VERSION 5.8 ;
BUSBITCHARS "[]" ;
DIVIDERCHAR "/" ;
UNITS
    DATABASE MICRONS 1000 ;
END UNITS

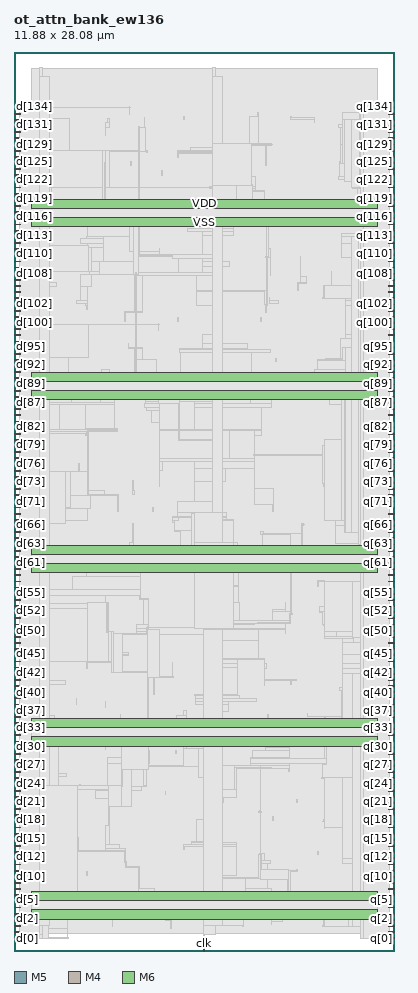
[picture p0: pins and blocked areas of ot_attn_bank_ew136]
MACRO ot_attn_bank_ew136
  FOREIGN ot_attn_bank_ew136 0 0 ;
  CLASS BLOCK ;
  SIZE 11.88 BY 28.08 ;
  PIN clk
    DIRECTION INPUT ;
    USE SIGNAL ;
    PORT
      LAYER M5 ;
        RECT  5.904 0 5.928 0.192 ;
    END
  END clk
  PIN d[0]
    DIRECTION INPUT ;
    USE SIGNAL ;
    PORT
      LAYER M4 ;
        RECT  0 0.384 0.192 0.408 ;
    END
  END d[0]
  PIN d[100]
    DIRECTION INPUT ;
    USE SIGNAL ;
    PORT
      LAYER M4 ;
        RECT  0 19.584 0.192 19.608 ;
    END
  END d[100]
  PIN d[101]
    DIRECTION INPUT ;
    USE SIGNAL ;
    PORT
      LAYER M4 ;
        RECT  0 19.776 0.192 19.8 ;
    END
  END d[101]
  PIN d[102]
    DIRECTION INPUT ;
    USE SIGNAL ;
    PORT
      LAYER M4 ;
        RECT  0 19.968 0.192 19.992 ;
    END
  END d[102]
  PIN d[103]
    DIRECTION INPUT ;
    USE SIGNAL ;
    PORT
      LAYER M4 ;
        RECT  0 20.16 0.192 20.184 ;
    END
  END d[103]
  PIN d[104]
    DIRECTION INPUT ;
    USE SIGNAL ;
    PORT
      LAYER M4 ;
        RECT  0 20.352 0.192 20.376 ;
    END
  END d[104]
  PIN d[105]
    DIRECTION INPUT ;
    USE SIGNAL ;
    PORT
      LAYER M4 ;
        RECT  0 20.544 0.192 20.568 ;
    END
  END d[105]
  PIN d[106]
    DIRECTION INPUT ;
    USE SIGNAL ;
    PORT
      LAYER M4 ;
        RECT  0 20.736 0.192 20.76 ;
    END
  END d[106]
  PIN d[107]
    DIRECTION INPUT ;
    USE SIGNAL ;
    PORT
      LAYER M4 ;
        RECT  0 20.928 0.192 20.952 ;
    END
  END d[107]
  PIN d[108]
    DIRECTION INPUT ;
    USE SIGNAL ;
    PORT
      LAYER M4 ;
        RECT  0 21.12 0.192 21.144 ;
    END
  END d[108]
  PIN d[109]
    DIRECTION INPUT ;
    USE SIGNAL ;
    PORT
      LAYER M4 ;
        RECT  0 21.312 0.192 21.336 ;
    END
  END d[109]
  PIN d[10]
    DIRECTION INPUT ;
    USE SIGNAL ;
    PORT
      LAYER M4 ;
        RECT  0 2.304 0.192 2.328 ;
    END
  END d[10]
  PIN d[110]
    DIRECTION INPUT ;
    USE SIGNAL ;
    PORT
      LAYER M4 ;
        RECT  0 21.504 0.192 21.528 ;
    END
  END d[110]
  PIN d[111]
    DIRECTION INPUT ;
    USE SIGNAL ;
    PORT
      LAYER M4 ;
        RECT  0 21.696 0.192 21.72 ;
    END
  END d[111]
  PIN d[112]
    DIRECTION INPUT ;
    USE SIGNAL ;
    PORT
      LAYER M4 ;
        RECT  0 21.888 0.192 21.912 ;
    END
  END d[112]
  PIN d[113]
    DIRECTION INPUT ;
    USE SIGNAL ;
    PORT
      LAYER M4 ;
        RECT  0 22.08 0.192 22.104 ;
    END
  END d[113]
  PIN d[114]
    DIRECTION INPUT ;
    USE SIGNAL ;
    PORT
      LAYER M4 ;
        RECT  0 22.272 0.192 22.296 ;
    END
  END d[114]
  PIN d[115]
    DIRECTION INPUT ;
    USE SIGNAL ;
    PORT
      LAYER M4 ;
        RECT  0 22.464 0.192 22.488 ;
    END
  END d[115]
  PIN d[116]
    DIRECTION INPUT ;
    USE SIGNAL ;
    PORT
      LAYER M4 ;
        RECT  0 22.656 0.192 22.68 ;
    END
  END d[116]
  PIN d[117]
    DIRECTION INPUT ;
    USE SIGNAL ;
    PORT
      LAYER M4 ;
        RECT  0 22.848 0.192 22.872 ;
    END
  END d[117]
  PIN d[118]
    DIRECTION INPUT ;
    USE SIGNAL ;
    PORT
      LAYER M4 ;
        RECT  0 23.04 0.192 23.064 ;
    END
  END d[118]
  PIN d[119]
    DIRECTION INPUT ;
    USE SIGNAL ;
    PORT
      LAYER M4 ;
        RECT  0 23.232 0.192 23.256 ;
    END
  END d[119]
  PIN d[11]
    DIRECTION INPUT ;
    USE SIGNAL ;
    PORT
      LAYER M4 ;
        RECT  0 2.496 0.192 2.52 ;
    END
  END d[11]
  PIN d[120]
    DIRECTION INPUT ;
    USE SIGNAL ;
    PORT
      LAYER M4 ;
        RECT  0 23.424 0.192 23.448 ;
    END
  END d[120]
  PIN d[121]
    DIRECTION INPUT ;
    USE SIGNAL ;
    PORT
      LAYER M4 ;
        RECT  0 23.616 0.192 23.64 ;
    END
  END d[121]
  PIN d[122]
    DIRECTION INPUT ;
    USE SIGNAL ;
    PORT
      LAYER M4 ;
        RECT  0 23.808 0.192 23.832 ;
    END
  END d[122]
  PIN d[123]
    DIRECTION INPUT ;
    USE SIGNAL ;
    PORT
      LAYER M4 ;
        RECT  0 24 0.192 24.024 ;
    END
  END d[123]
  PIN d[124]
    DIRECTION INPUT ;
    USE SIGNAL ;
    PORT
      LAYER M4 ;
        RECT  0 24.192 0.192 24.216 ;
    END
  END d[124]
  PIN d[125]
    DIRECTION INPUT ;
    USE SIGNAL ;
    PORT
      LAYER M4 ;
        RECT  0 24.384 0.192 24.408 ;
    END
  END d[125]
  PIN d[126]
    DIRECTION INPUT ;
    USE SIGNAL ;
    PORT
      LAYER M4 ;
        RECT  0 24.576 0.192 24.6 ;
    END
  END d[126]
  PIN d[127]
    DIRECTION INPUT ;
    USE SIGNAL ;
    PORT
      LAYER M4 ;
        RECT  0 24.768 0.192 24.792 ;
    END
  END d[127]
  PIN d[128]
    DIRECTION INPUT ;
    USE SIGNAL ;
    PORT
      LAYER M4 ;
        RECT  0 24.96 0.192 24.984 ;
    END
  END d[128]
  PIN d[129]
    DIRECTION INPUT ;
    USE SIGNAL ;
    PORT
      LAYER M4 ;
        RECT  0 25.152 0.192 25.176 ;
    END
  END d[129]
  PIN d[12]
    DIRECTION INPUT ;
    USE SIGNAL ;
    PORT
      LAYER M4 ;
        RECT  0 2.688 0.192 2.712 ;
    END
  END d[12]
  PIN d[130]
    DIRECTION INPUT ;
    USE SIGNAL ;
    PORT
      LAYER M4 ;
        RECT  0 25.344 0.192 25.368 ;
    END
  END d[130]
  PIN d[131]
    DIRECTION INPUT ;
    USE SIGNAL ;
    PORT
      LAYER M4 ;
        RECT  0 25.536 0.192 25.56 ;
    END
  END d[131]
  PIN d[132]
    DIRECTION INPUT ;
    USE SIGNAL ;
    PORT
      LAYER M4 ;
        RECT  0 25.728 0.192 25.752 ;
    END
  END d[132]
  PIN d[133]
    DIRECTION INPUT ;
    USE SIGNAL ;
    PORT
      LAYER M4 ;
        RECT  0 25.92 0.192 25.944 ;
    END
  END d[133]
  PIN d[134]
    DIRECTION INPUT ;
    USE SIGNAL ;
    PORT
      LAYER M4 ;
        RECT  0 26.112 0.192 26.136 ;
    END
  END d[134]
  PIN d[135]
    DIRECTION INPUT ;
    USE SIGNAL ;
    PORT
      LAYER M4 ;
        RECT  0 26.304 0.192 26.328 ;
    END
  END d[135]
  PIN d[13]
    DIRECTION INPUT ;
    USE SIGNAL ;
    PORT
      LAYER M4 ;
        RECT  0 2.88 0.192 2.904 ;
    END
  END d[13]
  PIN d[14]
    DIRECTION INPUT ;
    USE SIGNAL ;
    PORT
      LAYER M4 ;
        RECT  0 3.072 0.192 3.096 ;
    END
  END d[14]
  PIN d[15]
    DIRECTION INPUT ;
    USE SIGNAL ;
    PORT
      LAYER M4 ;
        RECT  0 3.264 0.192 3.288 ;
    END
  END d[15]
  PIN d[16]
    DIRECTION INPUT ;
    USE SIGNAL ;
    PORT
      LAYER M4 ;
        RECT  0 3.456 0.192 3.48 ;
    END
  END d[16]
  PIN d[17]
    DIRECTION INPUT ;
    USE SIGNAL ;
    PORT
      LAYER M4 ;
        RECT  0 3.648 0.192 3.672 ;
    END
  END d[17]
  PIN d[18]
    DIRECTION INPUT ;
    USE SIGNAL ;
    PORT
      LAYER M4 ;
        RECT  0 3.84 0.192 3.864 ;
    END
  END d[18]
  PIN d[19]
    DIRECTION INPUT ;
    USE SIGNAL ;
    PORT
      LAYER M4 ;
        RECT  0 4.032 0.192 4.056 ;
    END
  END d[19]
  PIN d[1]
    DIRECTION INPUT ;
    USE SIGNAL ;
    PORT
      LAYER M4 ;
        RECT  0 0.576 0.192 0.6 ;
    END
  END d[1]
  PIN d[20]
    DIRECTION INPUT ;
    USE SIGNAL ;
    PORT
      LAYER M4 ;
        RECT  0 4.224 0.192 4.248 ;
    END
  END d[20]
  PIN d[21]
    DIRECTION INPUT ;
    USE SIGNAL ;
    PORT
      LAYER M4 ;
        RECT  0 4.416 0.192 4.44 ;
    END
  END d[21]
  PIN d[22]
    DIRECTION INPUT ;
    USE SIGNAL ;
    PORT
      LAYER M4 ;
        RECT  0 4.608 0.192 4.632 ;
    END
  END d[22]
  PIN d[23]
    DIRECTION INPUT ;
    USE SIGNAL ;
    PORT
      LAYER M4 ;
        RECT  0 4.8 0.192 4.824 ;
    END
  END d[23]
  PIN d[24]
    DIRECTION INPUT ;
    USE SIGNAL ;
    PORT
      LAYER M4 ;
        RECT  0 4.992 0.192 5.016 ;
    END
  END d[24]
  PIN d[25]
    DIRECTION INPUT ;
    USE SIGNAL ;
    PORT
      LAYER M4 ;
        RECT  0 5.184 0.192 5.208 ;
    END
  END d[25]
  PIN d[26]
    DIRECTION INPUT ;
    USE SIGNAL ;
    PORT
      LAYER M4 ;
        RECT  0 5.376 0.192 5.4 ;
    END
  END d[26]
  PIN d[27]
    DIRECTION INPUT ;
    USE SIGNAL ;
    PORT
      LAYER M4 ;
        RECT  0 5.568 0.192 5.592 ;
    END
  END d[27]
  PIN d[28]
    DIRECTION INPUT ;
    USE SIGNAL ;
    PORT
      LAYER M4 ;
        RECT  0 5.76 0.192 5.784 ;
    END
  END d[28]
  PIN d[29]
    DIRECTION INPUT ;
    USE SIGNAL ;
    PORT
      LAYER M4 ;
        RECT  0 5.952 0.192 5.976 ;
    END
  END d[29]
  PIN d[2]
    DIRECTION INPUT ;
    USE SIGNAL ;
    PORT
      LAYER M4 ;
        RECT  0 0.768 0.192 0.792 ;
    END
  END d[2]
  PIN d[30]
    DIRECTION INPUT ;
    USE SIGNAL ;
    PORT
      LAYER M4 ;
        RECT  0 6.144 0.192 6.168 ;
    END
  END d[30]
  PIN d[31]
    DIRECTION INPUT ;
    USE SIGNAL ;
    PORT
      LAYER M4 ;
        RECT  0 6.336 0.192 6.36 ;
    END
  END d[31]
  PIN d[32]
    DIRECTION INPUT ;
    USE SIGNAL ;
    PORT
      LAYER M4 ;
        RECT  0 6.528 0.192 6.552 ;
    END
  END d[32]
  PIN d[33]
    DIRECTION INPUT ;
    USE SIGNAL ;
    PORT
      LAYER M4 ;
        RECT  0 6.72 0.192 6.744 ;
    END
  END d[33]
  PIN d[34]
    DIRECTION INPUT ;
    USE SIGNAL ;
    PORT
      LAYER M4 ;
        RECT  0 6.912 0.192 6.936 ;
    END
  END d[34]
  PIN d[35]
    DIRECTION INPUT ;
    USE SIGNAL ;
    PORT
      LAYER M4 ;
        RECT  0 7.104 0.192 7.128 ;
    END
  END d[35]
  PIN d[36]
    DIRECTION INPUT ;
    USE SIGNAL ;
    PORT
      LAYER M4 ;
        RECT  0 7.296 0.192 7.32 ;
    END
  END d[36]
  PIN d[37]
    DIRECTION INPUT ;
    USE SIGNAL ;
    PORT
      LAYER M4 ;
        RECT  0 7.488 0.192 7.512 ;
    END
  END d[37]
  PIN d[38]
    DIRECTION INPUT ;
    USE SIGNAL ;
    PORT
      LAYER M4 ;
        RECT  0 7.68 0.192 7.704 ;
    END
  END d[38]
  PIN d[39]
    DIRECTION INPUT ;
    USE SIGNAL ;
    PORT
      LAYER M4 ;
        RECT  0 7.872 0.192 7.896 ;
    END
  END d[39]
  PIN d[3]
    DIRECTION INPUT ;
    USE SIGNAL ;
    PORT
      LAYER M4 ;
        RECT  0 0.96 0.192 0.984 ;
    END
  END d[3]
  PIN d[40]
    DIRECTION INPUT ;
    USE SIGNAL ;
    PORT
      LAYER M4 ;
        RECT  0 8.064 0.192 8.088 ;
    END
  END d[40]
  PIN d[41]
    DIRECTION INPUT ;
    USE SIGNAL ;
    PORT
      LAYER M4 ;
        RECT  0 8.256 0.192 8.28 ;
    END
  END d[41]
  PIN d[42]
    DIRECTION INPUT ;
    USE SIGNAL ;
    PORT
      LAYER M4 ;
        RECT  0 8.448 0.192 8.472 ;
    END
  END d[42]
  PIN d[43]
    DIRECTION INPUT ;
    USE SIGNAL ;
    PORT
      LAYER M4 ;
        RECT  0 8.64 0.192 8.664 ;
    END
  END d[43]
  PIN d[44]
    DIRECTION INPUT ;
    USE SIGNAL ;
    PORT
      LAYER M4 ;
        RECT  0 8.832 0.192 8.856 ;
    END
  END d[44]
  PIN d[45]
    DIRECTION INPUT ;
    USE SIGNAL ;
    PORT
      LAYER M4 ;
        RECT  0 9.024 0.192 9.048 ;
    END
  END d[45]
  PIN d[46]
    DIRECTION INPUT ;
    USE SIGNAL ;
    PORT
      LAYER M4 ;
        RECT  0 9.216 0.192 9.24 ;
    END
  END d[46]
  PIN d[47]
    DIRECTION INPUT ;
    USE SIGNAL ;
    PORT
      LAYER M4 ;
        RECT  0 9.408 0.192 9.432 ;
    END
  END d[47]
  PIN d[48]
    DIRECTION INPUT ;
    USE SIGNAL ;
    PORT
      LAYER M4 ;
        RECT  0 9.6 0.192 9.624 ;
    END
  END d[48]
  PIN d[49]
    DIRECTION INPUT ;
    USE SIGNAL ;
    PORT
      LAYER M4 ;
        RECT  0 9.792 0.192 9.816 ;
    END
  END d[49]
  PIN d[4]
    DIRECTION INPUT ;
    USE SIGNAL ;
    PORT
      LAYER M4 ;
        RECT  0 1.152 0.192 1.176 ;
    END
  END d[4]
  PIN d[50]
    DIRECTION INPUT ;
    USE SIGNAL ;
    PORT
      LAYER M4 ;
        RECT  0 9.984 0.192 10.008 ;
    END
  END d[50]
  PIN d[51]
    DIRECTION INPUT ;
    USE SIGNAL ;
    PORT
      LAYER M4 ;
        RECT  0 10.176 0.192 10.2 ;
    END
  END d[51]
  PIN d[52]
    DIRECTION INPUT ;
    USE SIGNAL ;
    PORT
      LAYER M4 ;
        RECT  0 10.368 0.192 10.392 ;
    END
  END d[52]
  PIN d[53]
    DIRECTION INPUT ;
    USE SIGNAL ;
    PORT
      LAYER M4 ;
        RECT  0 10.56 0.192 10.584 ;
    END
  END d[53]
  PIN d[54]
    DIRECTION INPUT ;
    USE SIGNAL ;
    PORT
      LAYER M4 ;
        RECT  0 10.752 0.192 10.776 ;
    END
  END d[54]
  PIN d[55]
    DIRECTION INPUT ;
    USE SIGNAL ;
    PORT
      LAYER M4 ;
        RECT  0 10.944 0.192 10.968 ;
    END
  END d[55]
  PIN d[56]
    DIRECTION INPUT ;
    USE SIGNAL ;
    PORT
      LAYER M4 ;
        RECT  0 11.136 0.192 11.16 ;
    END
  END d[56]
  PIN d[57]
    DIRECTION INPUT ;
    USE SIGNAL ;
    PORT
      LAYER M4 ;
        RECT  0 11.328 0.192 11.352 ;
    END
  END d[57]
  PIN d[58]
    DIRECTION INPUT ;
    USE SIGNAL ;
    PORT
      LAYER M4 ;
        RECT  0 11.52 0.192 11.544 ;
    END
  END d[58]
  PIN d[59]
    DIRECTION INPUT ;
    USE SIGNAL ;
    PORT
      LAYER M4 ;
        RECT  0 11.712 0.192 11.736 ;
    END
  END d[59]
  PIN d[5]
    DIRECTION INPUT ;
    USE SIGNAL ;
    PORT
      LAYER M4 ;
        RECT  0 1.344 0.192 1.368 ;
    END
  END d[5]
  PIN d[60]
    DIRECTION INPUT ;
    USE SIGNAL ;
    PORT
      LAYER M4 ;
        RECT  0 11.904 0.192 11.928 ;
    END
  END d[60]
  PIN d[61]
    DIRECTION INPUT ;
    USE SIGNAL ;
    PORT
      LAYER M4 ;
        RECT  0 12.096 0.192 12.12 ;
    END
  END d[61]
  PIN d[62]
    DIRECTION INPUT ;
    USE SIGNAL ;
    PORT
      LAYER M4 ;
        RECT  0 12.288 0.192 12.312 ;
    END
  END d[62]
  PIN d[63]
    DIRECTION INPUT ;
    USE SIGNAL ;
    PORT
      LAYER M4 ;
        RECT  0 12.48 0.192 12.504 ;
    END
  END d[63]
  PIN d[64]
    DIRECTION INPUT ;
    USE SIGNAL ;
    PORT
      LAYER M4 ;
        RECT  0 12.672 0.192 12.696 ;
    END
  END d[64]
  PIN d[65]
    DIRECTION INPUT ;
    USE SIGNAL ;
    PORT
      LAYER M4 ;
        RECT  0 12.864 0.192 12.888 ;
    END
  END d[65]
  PIN d[66]
    DIRECTION INPUT ;
    USE SIGNAL ;
    PORT
      LAYER M4 ;
        RECT  0 13.056 0.192 13.08 ;
    END
  END d[66]
  PIN d[67]
    DIRECTION INPUT ;
    USE SIGNAL ;
    PORT
      LAYER M4 ;
        RECT  0 13.248 0.192 13.272 ;
    END
  END d[67]
  PIN d[68]
    DIRECTION INPUT ;
    USE SIGNAL ;
    PORT
      LAYER M4 ;
        RECT  0 13.44 0.192 13.464 ;
    END
  END d[68]
  PIN d[69]
    DIRECTION INPUT ;
    USE SIGNAL ;
    PORT
      LAYER M4 ;
        RECT  0 13.632 0.192 13.656 ;
    END
  END d[69]
  PIN d[6]
    DIRECTION INPUT ;
    USE SIGNAL ;
    PORT
      LAYER M4 ;
        RECT  0 1.536 0.192 1.56 ;
    END
  END d[6]
  PIN d[70]
    DIRECTION INPUT ;
    USE SIGNAL ;
    PORT
      LAYER M4 ;
        RECT  0 13.824 0.192 13.848 ;
    END
  END d[70]
  PIN d[71]
    DIRECTION INPUT ;
    USE SIGNAL ;
    PORT
      LAYER M4 ;
        RECT  0 14.016 0.192 14.04 ;
    END
  END d[71]
  PIN d[72]
    DIRECTION INPUT ;
    USE SIGNAL ;
    PORT
      LAYER M4 ;
        RECT  0 14.208 0.192 14.232 ;
    END
  END d[72]
  PIN d[73]
    DIRECTION INPUT ;
    USE SIGNAL ;
    PORT
      LAYER M4 ;
        RECT  0 14.4 0.192 14.424 ;
    END
  END d[73]
  PIN d[74]
    DIRECTION INPUT ;
    USE SIGNAL ;
    PORT
      LAYER M4 ;
        RECT  0 14.592 0.192 14.616 ;
    END
  END d[74]
  PIN d[75]
    DIRECTION INPUT ;
    USE SIGNAL ;
    PORT
      LAYER M4 ;
        RECT  0 14.784 0.192 14.808 ;
    END
  END d[75]
  PIN d[76]
    DIRECTION INPUT ;
    USE SIGNAL ;
    PORT
      LAYER M4 ;
        RECT  0 14.976 0.192 15 ;
    END
  END d[76]
  PIN d[77]
    DIRECTION INPUT ;
    USE SIGNAL ;
    PORT
      LAYER M4 ;
        RECT  0 15.168 0.192 15.192 ;
    END
  END d[77]
  PIN d[78]
    DIRECTION INPUT ;
    USE SIGNAL ;
    PORT
      LAYER M4 ;
        RECT  0 15.36 0.192 15.384 ;
    END
  END d[78]
  PIN d[79]
    DIRECTION INPUT ;
    USE SIGNAL ;
    PORT
      LAYER M4 ;
        RECT  0 15.552 0.192 15.576 ;
    END
  END d[79]
  PIN d[7]
    DIRECTION INPUT ;
    USE SIGNAL ;
    PORT
      LAYER M4 ;
        RECT  0 1.728 0.192 1.752 ;
    END
  END d[7]
  PIN d[80]
    DIRECTION INPUT ;
    USE SIGNAL ;
    PORT
      LAYER M4 ;
        RECT  0 15.744 0.192 15.768 ;
    END
  END d[80]
  PIN d[81]
    DIRECTION INPUT ;
    USE SIGNAL ;
    PORT
      LAYER M4 ;
        RECT  0 15.936 0.192 15.96 ;
    END
  END d[81]
  PIN d[82]
    DIRECTION INPUT ;
    USE SIGNAL ;
    PORT
      LAYER M4 ;
        RECT  0 16.128 0.192 16.152 ;
    END
  END d[82]
  PIN d[83]
    DIRECTION INPUT ;
    USE SIGNAL ;
    PORT
      LAYER M4 ;
        RECT  0 16.32 0.192 16.344 ;
    END
  END d[83]
  PIN d[84]
    DIRECTION INPUT ;
    USE SIGNAL ;
    PORT
      LAYER M4 ;
        RECT  0 16.512 0.192 16.536 ;
    END
  END d[84]
  PIN d[85]
    DIRECTION INPUT ;
    USE SIGNAL ;
    PORT
      LAYER M4 ;
        RECT  0 16.704 0.192 16.728 ;
    END
  END d[85]
  PIN d[86]
    DIRECTION INPUT ;
    USE SIGNAL ;
    PORT
      LAYER M4 ;
        RECT  0 16.896 0.192 16.92 ;
    END
  END d[86]
  PIN d[87]
    DIRECTION INPUT ;
    USE SIGNAL ;
    PORT
      LAYER M4 ;
        RECT  0 17.088 0.192 17.112 ;
    END
  END d[87]
  PIN d[88]
    DIRECTION INPUT ;
    USE SIGNAL ;
    PORT
      LAYER M4 ;
        RECT  0 17.28 0.192 17.304 ;
    END
  END d[88]
  PIN d[89]
    DIRECTION INPUT ;
    USE SIGNAL ;
    PORT
      LAYER M4 ;
        RECT  0 17.472 0.192 17.496 ;
    END
  END d[89]
  PIN d[8]
    DIRECTION INPUT ;
    USE SIGNAL ;
    PORT
      LAYER M4 ;
        RECT  0 1.92 0.192 1.944 ;
    END
  END d[8]
  PIN d[90]
    DIRECTION INPUT ;
    USE SIGNAL ;
    PORT
      LAYER M4 ;
        RECT  0 17.664 0.192 17.688 ;
    END
  END d[90]
  PIN d[91]
    DIRECTION INPUT ;
    USE SIGNAL ;
    PORT
      LAYER M4 ;
        RECT  0 17.856 0.192 17.88 ;
    END
  END d[91]
  PIN d[92]
    DIRECTION INPUT ;
    USE SIGNAL ;
    PORT
      LAYER M4 ;
        RECT  0 18.048 0.192 18.072 ;
    END
  END d[92]
  PIN d[93]
    DIRECTION INPUT ;
    USE SIGNAL ;
    PORT
      LAYER M4 ;
        RECT  0 18.24 0.192 18.264 ;
    END
  END d[93]
  PIN d[94]
    DIRECTION INPUT ;
    USE SIGNAL ;
    PORT
      LAYER M4 ;
        RECT  0 18.432 0.192 18.456 ;
    END
  END d[94]
  PIN d[95]
    DIRECTION INPUT ;
    USE SIGNAL ;
    PORT
      LAYER M4 ;
        RECT  0 18.624 0.192 18.648 ;
    END
  END d[95]
  PIN d[96]
    DIRECTION INPUT ;
    USE SIGNAL ;
    PORT
      LAYER M4 ;
        RECT  0 18.816 0.192 18.84 ;
    END
  END d[96]
  PIN d[97]
    DIRECTION INPUT ;
    USE SIGNAL ;
    PORT
      LAYER M4 ;
        RECT  0 19.008 0.192 19.032 ;
    END
  END d[97]
  PIN d[98]
    DIRECTION INPUT ;
    USE SIGNAL ;
    PORT
      LAYER M4 ;
        RECT  0 19.2 0.192 19.224 ;
    END
  END d[98]
  PIN d[99]
    DIRECTION INPUT ;
    USE SIGNAL ;
    PORT
      LAYER M4 ;
        RECT  0 19.392 0.192 19.416 ;
    END
  END d[99]
  PIN d[9]
    DIRECTION INPUT ;
    USE SIGNAL ;
    PORT
      LAYER M4 ;
        RECT  0 2.112 0.192 2.136 ;
    END
  END d[9]
  PIN q[0]
    DIRECTION OUTPUT ;
    USE SIGNAL ;
    PORT
      LAYER M4 ;
        RECT  11.688 0.384 11.88 0.408 ;
    END
  END q[0]
  PIN q[100]
    DIRECTION OUTPUT ;
    USE SIGNAL ;
    PORT
      LAYER M4 ;
        RECT  11.688 19.584 11.88 19.608 ;
    END
  END q[100]
  PIN q[101]
    DIRECTION OUTPUT ;
    USE SIGNAL ;
    PORT
      LAYER M4 ;
        RECT  11.688 19.776 11.88 19.8 ;
    END
  END q[101]
  PIN q[102]
    DIRECTION OUTPUT ;
    USE SIGNAL ;
    PORT
      LAYER M4 ;
        RECT  11.688 19.968 11.88 19.992 ;
    END
  END q[102]
  PIN q[103]
    DIRECTION OUTPUT ;
    USE SIGNAL ;
    PORT
      LAYER M4 ;
        RECT  11.688 20.16 11.88 20.184 ;
    END
  END q[103]
  PIN q[104]
    DIRECTION OUTPUT ;
    USE SIGNAL ;
    PORT
      LAYER M4 ;
        RECT  11.688 20.352 11.88 20.376 ;
    END
  END q[104]
  PIN q[105]
    DIRECTION OUTPUT ;
    USE SIGNAL ;
    PORT
      LAYER M4 ;
        RECT  11.688 20.544 11.88 20.568 ;
    END
  END q[105]
  PIN q[106]
    DIRECTION OUTPUT ;
    USE SIGNAL ;
    PORT
      LAYER M4 ;
        RECT  11.688 20.736 11.88 20.76 ;
    END
  END q[106]
  PIN q[107]
    DIRECTION OUTPUT ;
    USE SIGNAL ;
    PORT
      LAYER M4 ;
        RECT  11.688 20.928 11.88 20.952 ;
    END
  END q[107]
  PIN q[108]
    DIRECTION OUTPUT ;
    USE SIGNAL ;
    PORT
      LAYER M4 ;
        RECT  11.688 21.12 11.88 21.144 ;
    END
  END q[108]
  PIN q[109]
    DIRECTION OUTPUT ;
    USE SIGNAL ;
    PORT
      LAYER M4 ;
        RECT  11.688 21.312 11.88 21.336 ;
    END
  END q[109]
  PIN q[10]
    DIRECTION OUTPUT ;
    USE SIGNAL ;
    PORT
      LAYER M4 ;
        RECT  11.688 2.304 11.88 2.328 ;
    END
  END q[10]
  PIN q[110]
    DIRECTION OUTPUT ;
    USE SIGNAL ;
    PORT
      LAYER M4 ;
        RECT  11.688 21.504 11.88 21.528 ;
    END
  END q[110]
  PIN q[111]
    DIRECTION OUTPUT ;
    USE SIGNAL ;
    PORT
      LAYER M4 ;
        RECT  11.688 21.696 11.88 21.72 ;
    END
  END q[111]
  PIN q[112]
    DIRECTION OUTPUT ;
    USE SIGNAL ;
    PORT
      LAYER M4 ;
        RECT  11.688 21.888 11.88 21.912 ;
    END
  END q[112]
  PIN q[113]
    DIRECTION OUTPUT ;
    USE SIGNAL ;
    PORT
      LAYER M4 ;
        RECT  11.688 22.08 11.88 22.104 ;
    END
  END q[113]
  PIN q[114]
    DIRECTION OUTPUT ;
    USE SIGNAL ;
    PORT
      LAYER M4 ;
        RECT  11.688 22.272 11.88 22.296 ;
    END
  END q[114]
  PIN q[115]
    DIRECTION OUTPUT ;
    USE SIGNAL ;
    PORT
      LAYER M4 ;
        RECT  11.688 22.464 11.88 22.488 ;
    END
  END q[115]
  PIN q[116]
    DIRECTION OUTPUT ;
    USE SIGNAL ;
    PORT
      LAYER M4 ;
        RECT  11.688 22.656 11.88 22.68 ;
    END
  END q[116]
  PIN q[117]
    DIRECTION OUTPUT ;
    USE SIGNAL ;
    PORT
      LAYER M4 ;
        RECT  11.688 22.848 11.88 22.872 ;
    END
  END q[117]
  PIN q[118]
    DIRECTION OUTPUT ;
    USE SIGNAL ;
    PORT
      LAYER M4 ;
        RECT  11.688 23.04 11.88 23.064 ;
    END
  END q[118]
  PIN q[119]
    DIRECTION OUTPUT ;
    USE SIGNAL ;
    PORT
      LAYER M4 ;
        RECT  11.688 23.232 11.88 23.256 ;
    END
  END q[119]
  PIN q[11]
    DIRECTION OUTPUT ;
    USE SIGNAL ;
    PORT
      LAYER M4 ;
        RECT  11.688 2.496 11.88 2.52 ;
    END
  END q[11]
  PIN q[120]
    DIRECTION OUTPUT ;
    USE SIGNAL ;
    PORT
      LAYER M4 ;
        RECT  11.688 23.424 11.88 23.448 ;
    END
  END q[120]
  PIN q[121]
    DIRECTION OUTPUT ;
    USE SIGNAL ;
    PORT
      LAYER M4 ;
        RECT  11.688 23.616 11.88 23.64 ;
    END
  END q[121]
  PIN q[122]
    DIRECTION OUTPUT ;
    USE SIGNAL ;
    PORT
      LAYER M4 ;
        RECT  11.688 23.808 11.88 23.832 ;
    END
  END q[122]
  PIN q[123]
    DIRECTION OUTPUT ;
    USE SIGNAL ;
    PORT
      LAYER M4 ;
        RECT  11.688 24 11.88 24.024 ;
    END
  END q[123]
  PIN q[124]
    DIRECTION OUTPUT ;
    USE SIGNAL ;
    PORT
      LAYER M4 ;
        RECT  11.688 24.192 11.88 24.216 ;
    END
  END q[124]
  PIN q[125]
    DIRECTION OUTPUT ;
    USE SIGNAL ;
    PORT
      LAYER M4 ;
        RECT  11.688 24.384 11.88 24.408 ;
    END
  END q[125]
  PIN q[126]
    DIRECTION OUTPUT ;
    USE SIGNAL ;
    PORT
      LAYER M4 ;
        RECT  11.688 24.576 11.88 24.6 ;
    END
  END q[126]
  PIN q[127]
    DIRECTION OUTPUT ;
    USE SIGNAL ;
    PORT
      LAYER M4 ;
        RECT  11.688 24.768 11.88 24.792 ;
    END
  END q[127]
  PIN q[128]
    DIRECTION OUTPUT ;
    USE SIGNAL ;
    PORT
      LAYER M4 ;
        RECT  11.688 24.96 11.88 24.984 ;
    END
  END q[128]
  PIN q[129]
    DIRECTION OUTPUT ;
    USE SIGNAL ;
    PORT
      LAYER M4 ;
        RECT  11.688 25.152 11.88 25.176 ;
    END
  END q[129]
  PIN q[12]
    DIRECTION OUTPUT ;
    USE SIGNAL ;
    PORT
      LAYER M4 ;
        RECT  11.688 2.688 11.88 2.712 ;
    END
  END q[12]
  PIN q[130]
    DIRECTION OUTPUT ;
    USE SIGNAL ;
    PORT
      LAYER M4 ;
        RECT  11.688 25.344 11.88 25.368 ;
    END
  END q[130]
  PIN q[131]
    DIRECTION OUTPUT ;
    USE SIGNAL ;
    PORT
      LAYER M4 ;
        RECT  11.688 25.536 11.88 25.56 ;
    END
  END q[131]
  PIN q[132]
    DIRECTION OUTPUT ;
    USE SIGNAL ;
    PORT
      LAYER M4 ;
        RECT  11.688 25.728 11.88 25.752 ;
    END
  END q[132]
  PIN q[133]
    DIRECTION OUTPUT ;
    USE SIGNAL ;
    PORT
      LAYER M4 ;
        RECT  11.688 25.92 11.88 25.944 ;
    END
  END q[133]
  PIN q[134]
    DIRECTION OUTPUT ;
    USE SIGNAL ;
    PORT
      LAYER M4 ;
        RECT  11.688 26.112 11.88 26.136 ;
    END
  END q[134]
  PIN q[135]
    DIRECTION OUTPUT ;
    USE SIGNAL ;
    PORT
      LAYER M4 ;
        RECT  11.688 26.304 11.88 26.328 ;
    END
  END q[135]
  PIN q[13]
    DIRECTION OUTPUT ;
    USE SIGNAL ;
    PORT
      LAYER M4 ;
        RECT  11.688 2.88 11.88 2.904 ;
    END
  END q[13]
  PIN q[14]
    DIRECTION OUTPUT ;
    USE SIGNAL ;
    PORT
      LAYER M4 ;
        RECT  11.688 3.072 11.88 3.096 ;
    END
  END q[14]
  PIN q[15]
    DIRECTION OUTPUT ;
    USE SIGNAL ;
    PORT
      LAYER M4 ;
        RECT  11.688 3.264 11.88 3.288 ;
    END
  END q[15]
  PIN q[16]
    DIRECTION OUTPUT ;
    USE SIGNAL ;
    PORT
      LAYER M4 ;
        RECT  11.688 3.456 11.88 3.48 ;
    END
  END q[16]
  PIN q[17]
    DIRECTION OUTPUT ;
    USE SIGNAL ;
    PORT
      LAYER M4 ;
        RECT  11.688 3.648 11.88 3.672 ;
    END
  END q[17]
  PIN q[18]
    DIRECTION OUTPUT ;
    USE SIGNAL ;
    PORT
      LAYER M4 ;
        RECT  11.688 3.84 11.88 3.864 ;
    END
  END q[18]
  PIN q[19]
    DIRECTION OUTPUT ;
    USE SIGNAL ;
    PORT
      LAYER M4 ;
        RECT  11.688 4.032 11.88 4.056 ;
    END
  END q[19]
  PIN q[1]
    DIRECTION OUTPUT ;
    USE SIGNAL ;
    PORT
      LAYER M4 ;
        RECT  11.688 0.576 11.88 0.6 ;
    END
  END q[1]
  PIN q[20]
    DIRECTION OUTPUT ;
    USE SIGNAL ;
    PORT
      LAYER M4 ;
        RECT  11.688 4.224 11.88 4.248 ;
    END
  END q[20]
  PIN q[21]
    DIRECTION OUTPUT ;
    USE SIGNAL ;
    PORT
      LAYER M4 ;
        RECT  11.688 4.416 11.88 4.44 ;
    END
  END q[21]
  PIN q[22]
    DIRECTION OUTPUT ;
    USE SIGNAL ;
    PORT
      LAYER M4 ;
        RECT  11.688 4.608 11.88 4.632 ;
    END
  END q[22]
  PIN q[23]
    DIRECTION OUTPUT ;
    USE SIGNAL ;
    PORT
      LAYER M4 ;
        RECT  11.688 4.8 11.88 4.824 ;
    END
  END q[23]
  PIN q[24]
    DIRECTION OUTPUT ;
    USE SIGNAL ;
    PORT
      LAYER M4 ;
        RECT  11.688 4.992 11.88 5.016 ;
    END
  END q[24]
  PIN q[25]
    DIRECTION OUTPUT ;
    USE SIGNAL ;
    PORT
      LAYER M4 ;
        RECT  11.688 5.184 11.88 5.208 ;
    END
  END q[25]
  PIN q[26]
    DIRECTION OUTPUT ;
    USE SIGNAL ;
    PORT
      LAYER M4 ;
        RECT  11.688 5.376 11.88 5.4 ;
    END
  END q[26]
  PIN q[27]
    DIRECTION OUTPUT ;
    USE SIGNAL ;
    PORT
      LAYER M4 ;
        RECT  11.688 5.568 11.88 5.592 ;
    END
  END q[27]
  PIN q[28]
    DIRECTION OUTPUT ;
    USE SIGNAL ;
    PORT
      LAYER M4 ;
        RECT  11.688 5.76 11.88 5.784 ;
    END
  END q[28]
  PIN q[29]
    DIRECTION OUTPUT ;
    USE SIGNAL ;
    PORT
      LAYER M4 ;
        RECT  11.688 5.952 11.88 5.976 ;
    END
  END q[29]
  PIN q[2]
    DIRECTION OUTPUT ;
    USE SIGNAL ;
    PORT
      LAYER M4 ;
        RECT  11.688 0.768 11.88 0.792 ;
    END
  END q[2]
  PIN q[30]
    DIRECTION OUTPUT ;
    USE SIGNAL ;
    PORT
      LAYER M4 ;
        RECT  11.688 6.144 11.88 6.168 ;
    END
  END q[30]
  PIN q[31]
    DIRECTION OUTPUT ;
    USE SIGNAL ;
    PORT
      LAYER M4 ;
        RECT  11.688 6.336 11.88 6.36 ;
    END
  END q[31]
  PIN q[32]
    DIRECTION OUTPUT ;
    USE SIGNAL ;
    PORT
      LAYER M4 ;
        RECT  11.688 6.528 11.88 6.552 ;
    END
  END q[32]
  PIN q[33]
    DIRECTION OUTPUT ;
    USE SIGNAL ;
    PORT
      LAYER M4 ;
        RECT  11.688 6.72 11.88 6.744 ;
    END
  END q[33]
  PIN q[34]
    DIRECTION OUTPUT ;
    USE SIGNAL ;
    PORT
      LAYER M4 ;
        RECT  11.688 6.912 11.88 6.936 ;
    END
  END q[34]
  PIN q[35]
    DIRECTION OUTPUT ;
    USE SIGNAL ;
    PORT
      LAYER M4 ;
        RECT  11.688 7.104 11.88 7.128 ;
    END
  END q[35]
  PIN q[36]
    DIRECTION OUTPUT ;
    USE SIGNAL ;
    PORT
      LAYER M4 ;
        RECT  11.688 7.296 11.88 7.32 ;
    END
  END q[36]
  PIN q[37]
    DIRECTION OUTPUT ;
    USE SIGNAL ;
    PORT
      LAYER M4 ;
        RECT  11.688 7.488 11.88 7.512 ;
    END
  END q[37]
  PIN q[38]
    DIRECTION OUTPUT ;
    USE SIGNAL ;
    PORT
      LAYER M4 ;
        RECT  11.688 7.68 11.88 7.704 ;
    END
  END q[38]
  PIN q[39]
    DIRECTION OUTPUT ;
    USE SIGNAL ;
    PORT
      LAYER M4 ;
        RECT  11.688 7.872 11.88 7.896 ;
    END
  END q[39]
  PIN q[3]
    DIRECTION OUTPUT ;
    USE SIGNAL ;
    PORT
      LAYER M4 ;
        RECT  11.688 0.96 11.88 0.984 ;
    END
  END q[3]
  PIN q[40]
    DIRECTION OUTPUT ;
    USE SIGNAL ;
    PORT
      LAYER M4 ;
        RECT  11.688 8.064 11.88 8.088 ;
    END
  END q[40]
  PIN q[41]
    DIRECTION OUTPUT ;
    USE SIGNAL ;
    PORT
      LAYER M4 ;
        RECT  11.688 8.256 11.88 8.28 ;
    END
  END q[41]
  PIN q[42]
    DIRECTION OUTPUT ;
    USE SIGNAL ;
    PORT
      LAYER M4 ;
        RECT  11.688 8.448 11.88 8.472 ;
    END
  END q[42]
  PIN q[43]
    DIRECTION OUTPUT ;
    USE SIGNAL ;
    PORT
      LAYER M4 ;
        RECT  11.688 8.64 11.88 8.664 ;
    END
  END q[43]
  PIN q[44]
    DIRECTION OUTPUT ;
    USE SIGNAL ;
    PORT
      LAYER M4 ;
        RECT  11.688 8.832 11.88 8.856 ;
    END
  END q[44]
  PIN q[45]
    DIRECTION OUTPUT ;
    USE SIGNAL ;
    PORT
      LAYER M4 ;
        RECT  11.688 9.024 11.88 9.048 ;
    END
  END q[45]
  PIN q[46]
    DIRECTION OUTPUT ;
    USE SIGNAL ;
    PORT
      LAYER M4 ;
        RECT  11.688 9.216 11.88 9.24 ;
    END
  END q[46]
  PIN q[47]
    DIRECTION OUTPUT ;
    USE SIGNAL ;
    PORT
      LAYER M4 ;
        RECT  11.688 9.408 11.88 9.432 ;
    END
  END q[47]
  PIN q[48]
    DIRECTION OUTPUT ;
    USE SIGNAL ;
    PORT
      LAYER M4 ;
        RECT  11.688 9.6 11.88 9.624 ;
    END
  END q[48]
  PIN q[49]
    DIRECTION OUTPUT ;
    USE SIGNAL ;
    PORT
      LAYER M4 ;
        RECT  11.688 9.792 11.88 9.816 ;
    END
  END q[49]
  PIN q[4]
    DIRECTION OUTPUT ;
    USE SIGNAL ;
    PORT
      LAYER M4 ;
        RECT  11.688 1.152 11.88 1.176 ;
    END
  END q[4]
  PIN q[50]
    DIRECTION OUTPUT ;
    USE SIGNAL ;
    PORT
      LAYER M4 ;
        RECT  11.688 9.984 11.88 10.008 ;
    END
  END q[50]
  PIN q[51]
    DIRECTION OUTPUT ;
    USE SIGNAL ;
    PORT
      LAYER M4 ;
        RECT  11.688 10.176 11.88 10.2 ;
    END
  END q[51]
  PIN q[52]
    DIRECTION OUTPUT ;
    USE SIGNAL ;
    PORT
      LAYER M4 ;
        RECT  11.688 10.368 11.88 10.392 ;
    END
  END q[52]
  PIN q[53]
    DIRECTION OUTPUT ;
    USE SIGNAL ;
    PORT
      LAYER M4 ;
        RECT  11.688 10.56 11.88 10.584 ;
    END
  END q[53]
  PIN q[54]
    DIRECTION OUTPUT ;
    USE SIGNAL ;
    PORT
      LAYER M4 ;
        RECT  11.688 10.752 11.88 10.776 ;
    END
  END q[54]
  PIN q[55]
    DIRECTION OUTPUT ;
    USE SIGNAL ;
    PORT
      LAYER M4 ;
        RECT  11.688 10.944 11.88 10.968 ;
    END
  END q[55]
  PIN q[56]
    DIRECTION OUTPUT ;
    USE SIGNAL ;
    PORT
      LAYER M4 ;
        RECT  11.688 11.136 11.88 11.16 ;
    END
  END q[56]
  PIN q[57]
    DIRECTION OUTPUT ;
    USE SIGNAL ;
    PORT
      LAYER M4 ;
        RECT  11.688 11.328 11.88 11.352 ;
    END
  END q[57]
  PIN q[58]
    DIRECTION OUTPUT ;
    USE SIGNAL ;
    PORT
      LAYER M4 ;
        RECT  11.688 11.52 11.88 11.544 ;
    END
  END q[58]
  PIN q[59]
    DIRECTION OUTPUT ;
    USE SIGNAL ;
    PORT
      LAYER M4 ;
        RECT  11.688 11.712 11.88 11.736 ;
    END
  END q[59]
  PIN q[5]
    DIRECTION OUTPUT ;
    USE SIGNAL ;
    PORT
      LAYER M4 ;
        RECT  11.688 1.344 11.88 1.368 ;
    END
  END q[5]
  PIN q[60]
    DIRECTION OUTPUT ;
    USE SIGNAL ;
    PORT
      LAYER M4 ;
        RECT  11.688 11.904 11.88 11.928 ;
    END
  END q[60]
  PIN q[61]
    DIRECTION OUTPUT ;
    USE SIGNAL ;
    PORT
      LAYER M4 ;
        RECT  11.688 12.096 11.88 12.12 ;
    END
  END q[61]
  PIN q[62]
    DIRECTION OUTPUT ;
    USE SIGNAL ;
    PORT
      LAYER M4 ;
        RECT  11.688 12.288 11.88 12.312 ;
    END
  END q[62]
  PIN q[63]
    DIRECTION OUTPUT ;
    USE SIGNAL ;
    PORT
      LAYER M4 ;
        RECT  11.688 12.48 11.88 12.504 ;
    END
  END q[63]
  PIN q[64]
    DIRECTION OUTPUT ;
    USE SIGNAL ;
    PORT
      LAYER M4 ;
        RECT  11.688 12.672 11.88 12.696 ;
    END
  END q[64]
  PIN q[65]
    DIRECTION OUTPUT ;
    USE SIGNAL ;
    PORT
      LAYER M4 ;
        RECT  11.688 12.864 11.88 12.888 ;
    END
  END q[65]
  PIN q[66]
    DIRECTION OUTPUT ;
    USE SIGNAL ;
    PORT
      LAYER M4 ;
        RECT  11.688 13.056 11.88 13.08 ;
    END
  END q[66]
  PIN q[67]
    DIRECTION OUTPUT ;
    USE SIGNAL ;
    PORT
      LAYER M4 ;
        RECT  11.688 13.248 11.88 13.272 ;
    END
  END q[67]
  PIN q[68]
    DIRECTION OUTPUT ;
    USE SIGNAL ;
    PORT
      LAYER M4 ;
        RECT  11.688 13.44 11.88 13.464 ;
    END
  END q[68]
  PIN q[69]
    DIRECTION OUTPUT ;
    USE SIGNAL ;
    PORT
      LAYER M4 ;
        RECT  11.688 13.632 11.88 13.656 ;
    END
  END q[69]
  PIN q[6]
    DIRECTION OUTPUT ;
    USE SIGNAL ;
    PORT
      LAYER M4 ;
        RECT  11.688 1.536 11.88 1.56 ;
    END
  END q[6]
  PIN q[70]
    DIRECTION OUTPUT ;
    USE SIGNAL ;
    PORT
      LAYER M4 ;
        RECT  11.688 13.824 11.88 13.848 ;
    END
  END q[70]
  PIN q[71]
    DIRECTION OUTPUT ;
    USE SIGNAL ;
    PORT
      LAYER M4 ;
        RECT  11.688 14.016 11.88 14.04 ;
    END
  END q[71]
  PIN q[72]
    DIRECTION OUTPUT ;
    USE SIGNAL ;
    PORT
      LAYER M4 ;
        RECT  11.688 14.208 11.88 14.232 ;
    END
  END q[72]
  PIN q[73]
    DIRECTION OUTPUT ;
    USE SIGNAL ;
    PORT
      LAYER M4 ;
        RECT  11.688 14.4 11.88 14.424 ;
    END
  END q[73]
  PIN q[74]
    DIRECTION OUTPUT ;
    USE SIGNAL ;
    PORT
      LAYER M4 ;
        RECT  11.688 14.592 11.88 14.616 ;
    END
  END q[74]
  PIN q[75]
    DIRECTION OUTPUT ;
    USE SIGNAL ;
    PORT
      LAYER M4 ;
        RECT  11.688 14.784 11.88 14.808 ;
    END
  END q[75]
  PIN q[76]
    DIRECTION OUTPUT ;
    USE SIGNAL ;
    PORT
      LAYER M4 ;
        RECT  11.688 14.976 11.88 15 ;
    END
  END q[76]
  PIN q[77]
    DIRECTION OUTPUT ;
    USE SIGNAL ;
    PORT
      LAYER M4 ;
        RECT  11.688 15.168 11.88 15.192 ;
    END
  END q[77]
  PIN q[78]
    DIRECTION OUTPUT ;
    USE SIGNAL ;
    PORT
      LAYER M4 ;
        RECT  11.688 15.36 11.88 15.384 ;
    END
  END q[78]
  PIN q[79]
    DIRECTION OUTPUT ;
    USE SIGNAL ;
    PORT
      LAYER M4 ;
        RECT  11.688 15.552 11.88 15.576 ;
    END
  END q[79]
  PIN q[7]
    DIRECTION OUTPUT ;
    USE SIGNAL ;
    PORT
      LAYER M4 ;
        RECT  11.688 1.728 11.88 1.752 ;
    END
  END q[7]
  PIN q[80]
    DIRECTION OUTPUT ;
    USE SIGNAL ;
    PORT
      LAYER M4 ;
        RECT  11.688 15.744 11.88 15.768 ;
    END
  END q[80]
  PIN q[81]
    DIRECTION OUTPUT ;
    USE SIGNAL ;
    PORT
      LAYER M4 ;
        RECT  11.688 15.936 11.88 15.96 ;
    END
  END q[81]
  PIN q[82]
    DIRECTION OUTPUT ;
    USE SIGNAL ;
    PORT
      LAYER M4 ;
        RECT  11.688 16.128 11.88 16.152 ;
    END
  END q[82]
  PIN q[83]
    DIRECTION OUTPUT ;
    USE SIGNAL ;
    PORT
      LAYER M4 ;
        RECT  11.688 16.32 11.88 16.344 ;
    END
  END q[83]
  PIN q[84]
    DIRECTION OUTPUT ;
    USE SIGNAL ;
    PORT
      LAYER M4 ;
        RECT  11.688 16.512 11.88 16.536 ;
    END
  END q[84]
  PIN q[85]
    DIRECTION OUTPUT ;
    USE SIGNAL ;
    PORT
      LAYER M4 ;
        RECT  11.688 16.704 11.88 16.728 ;
    END
  END q[85]
  PIN q[86]
    DIRECTION OUTPUT ;
    USE SIGNAL ;
    PORT
      LAYER M4 ;
        RECT  11.688 16.896 11.88 16.92 ;
    END
  END q[86]
  PIN q[87]
    DIRECTION OUTPUT ;
    USE SIGNAL ;
    PORT
      LAYER M4 ;
        RECT  11.688 17.088 11.88 17.112 ;
    END
  END q[87]
  PIN q[88]
    DIRECTION OUTPUT ;
    USE SIGNAL ;
    PORT
      LAYER M4 ;
        RECT  11.688 17.28 11.88 17.304 ;
    END
  END q[88]
  PIN q[89]
    DIRECTION OUTPUT ;
    USE SIGNAL ;
    PORT
      LAYER M4 ;
        RECT  11.688 17.472 11.88 17.496 ;
    END
  END q[89]
  PIN q[8]
    DIRECTION OUTPUT ;
    USE SIGNAL ;
    PORT
      LAYER M4 ;
        RECT  11.688 1.92 11.88 1.944 ;
    END
  END q[8]
  PIN q[90]
    DIRECTION OUTPUT ;
    USE SIGNAL ;
    PORT
      LAYER M4 ;
        RECT  11.688 17.664 11.88 17.688 ;
    END
  END q[90]
  PIN q[91]
    DIRECTION OUTPUT ;
    USE SIGNAL ;
    PORT
      LAYER M4 ;
        RECT  11.688 17.856 11.88 17.88 ;
    END
  END q[91]
  PIN q[92]
    DIRECTION OUTPUT ;
    USE SIGNAL ;
    PORT
      LAYER M4 ;
        RECT  11.688 18.048 11.88 18.072 ;
    END
  END q[92]
  PIN q[93]
    DIRECTION OUTPUT ;
    USE SIGNAL ;
    PORT
      LAYER M4 ;
        RECT  11.688 18.24 11.88 18.264 ;
    END
  END q[93]
  PIN q[94]
    DIRECTION OUTPUT ;
    USE SIGNAL ;
    PORT
      LAYER M4 ;
        RECT  11.688 18.432 11.88 18.456 ;
    END
  END q[94]
  PIN q[95]
    DIRECTION OUTPUT ;
    USE SIGNAL ;
    PORT
      LAYER M4 ;
        RECT  11.688 18.624 11.88 18.648 ;
    END
  END q[95]
  PIN q[96]
    DIRECTION OUTPUT ;
    USE SIGNAL ;
    PORT
      LAYER M4 ;
        RECT  11.688 18.816 11.88 18.84 ;
    END
  END q[96]
  PIN q[97]
    DIRECTION OUTPUT ;
    USE SIGNAL ;
    PORT
      LAYER M4 ;
        RECT  11.688 19.008 11.88 19.032 ;
    END
  END q[97]
  PIN q[98]
    DIRECTION OUTPUT ;
    USE SIGNAL ;
    PORT
      LAYER M4 ;
        RECT  11.688 19.2 11.88 19.224 ;
    END
  END q[98]
  PIN q[99]
    DIRECTION OUTPUT ;
    USE SIGNAL ;
    PORT
      LAYER M4 ;
        RECT  11.688 19.392 11.88 19.416 ;
    END
  END q[99]
  PIN q[9]
    DIRECTION OUTPUT ;
    USE SIGNAL ;
    PORT
      LAYER M4 ;
        RECT  11.688 2.112 11.88 2.136 ;
    END
  END q[9]
  PIN VDD
    DIRECTION INOUT ;
    USE POWER ;
    PORT
      LAYER M6 ;
        RECT  0.54 23.172 11.34 23.46 ;
        RECT  0.54 17.772 11.34 18.06 ;
        RECT  0.54 12.372 11.34 12.66 ;
        RECT  0.54 6.972 11.34 7.26 ;
        RECT  0.54 1.572 11.34 1.86 ;
    END
  END VDD
  PIN VSS
    DIRECTION INOUT ;
    USE GROUND ;
    PORT
      LAYER M6 ;
        RECT  0.54 22.596 11.34 22.884 ;
        RECT  0.54 17.196 11.34 17.484 ;
        RECT  0.54 11.796 11.34 12.084 ;
        RECT  0.54 6.396 11.34 6.684 ;
        RECT  0.54 0.996 11.34 1.284 ;
    END
  END VSS
  OBS
    LAYER RVTN ;
     RECT  0.54 0.54 11.34 0.675 ;
     RECT  0.54 0.945 11.34 1.215 ;
     RECT  0.54 1.485 11.34 1.755 ;
     RECT  0.54 2.025 11.34 2.295 ;
     RECT  0.54 2.565 11.34 2.835 ;
     RECT  0.54 3.105 11.34 3.375 ;
     RECT  0.54 3.645 11.34 3.915 ;
     RECT  0.54 4.185 11.34 4.455 ;
     RECT  0.54 4.725 11.34 4.995 ;
     RECT  0.54 5.265 11.34 5.535 ;
     RECT  0.54 5.805 11.34 6.075 ;
     RECT  0.54 6.345 11.34 6.615 ;
     RECT  0.54 6.885 11.34 7.155 ;
     RECT  0.54 7.425 11.34 7.695 ;
     RECT  0.54 7.965 11.34 8.235 ;
     RECT  0.54 8.505 11.34 8.775 ;
     RECT  0.54 9.045 11.34 9.315 ;
     RECT  0.54 9.585 11.34 9.855 ;
     RECT  0.54 10.125 11.34 10.395 ;
     RECT  0.54 10.665 11.34 10.935 ;
     RECT  0.54 11.205 11.34 11.475 ;
     RECT  0.54 11.745 11.34 12.015 ;
     RECT  0.54 12.285 11.34 12.555 ;
     RECT  0.54 12.825 11.34 13.095 ;
     RECT  0.54 13.365 11.34 13.635 ;
     RECT  0.54 13.905 11.34 14.175 ;
     RECT  0.54 14.445 11.34 14.715 ;
     RECT  0.54 14.985 11.34 15.255 ;
     RECT  0.54 15.525 11.34 15.795 ;
     RECT  0.54 16.065 11.34 16.335 ;
     RECT  0.54 16.605 11.34 16.875 ;
     RECT  0.54 17.145 11.34 17.415 ;
     RECT  0.54 17.685 11.34 17.955 ;
     RECT  0.54 18.225 11.34 18.495 ;
     RECT  0.54 18.765 11.34 19.035 ;
     RECT  0.54 19.305 11.34 19.575 ;
     RECT  0.54 19.845 11.34 20.115 ;
     RECT  0.54 20.385 11.34 20.655 ;
     RECT  0.54 20.925 11.34 21.195 ;
     RECT  0.54 21.465 11.34 21.735 ;
     RECT  0.54 22.005 11.34 22.275 ;
     RECT  0.54 22.545 11.34 22.815 ;
     RECT  0.54 23.085 11.34 23.355 ;
     RECT  0.54 23.625 11.34 23.895 ;
     RECT  0.54 24.165 11.34 24.435 ;
     RECT  0.54 24.705 11.34 24.975 ;
     RECT  0.54 25.245 11.34 25.515 ;
     RECT  0.54 25.785 11.34 26.055 ;
     RECT  0.54 26.325 11.34 26.595 ;
     RECT  0.54 26.865 11.34 27.135 ;
     RECT  0.54 27.405 11.34 27.54 ;
    LAYER RVTP ;
     RECT  0.54 0.675 11.34 0.945 ;
     RECT  0.54 1.215 11.34 1.485 ;
     RECT  0.54 1.755 11.34 2.025 ;
     RECT  0.54 2.295 11.34 2.565 ;
     RECT  0.54 2.835 11.34 3.105 ;
     RECT  0.54 3.375 11.34 3.645 ;
     RECT  0.54 3.915 11.34 4.185 ;
     RECT  0.54 4.455 11.34 4.725 ;
     RECT  0.54 4.995 11.34 5.265 ;
     RECT  0.54 5.535 11.34 5.805 ;
     RECT  0.54 6.075 11.34 6.345 ;
     RECT  0.54 6.615 11.34 6.885 ;
     RECT  0.54 7.155 11.34 7.425 ;
     RECT  0.54 7.695 11.34 7.965 ;
     RECT  0.54 8.235 11.34 8.505 ;
     RECT  0.54 8.775 11.34 9.045 ;
     RECT  0.54 9.315 11.34 9.585 ;
     RECT  0.54 9.855 11.34 10.125 ;
     RECT  0.54 10.395 11.34 10.665 ;
     RECT  0.54 10.935 11.34 11.205 ;
     RECT  0.54 11.475 11.34 11.745 ;
     RECT  0.54 12.015 11.34 12.285 ;
     RECT  0.54 12.555 11.34 12.825 ;
     RECT  0.54 13.095 11.34 13.365 ;
     RECT  0.54 13.635 11.34 13.905 ;
     RECT  0.54 14.175 11.34 14.445 ;
     RECT  0.54 14.715 11.34 14.985 ;
     RECT  0.54 15.255 11.34 15.525 ;
     RECT  0.54 15.795 11.34 16.065 ;
     RECT  0.54 16.335 11.34 16.605 ;
     RECT  0.54 16.875 11.34 17.145 ;
     RECT  0.54 17.415 11.34 17.685 ;
     RECT  0.54 17.955 11.34 18.225 ;
     RECT  0.54 18.495 11.34 18.765 ;
     RECT  0.54 19.035 11.34 19.305 ;
     RECT  0.54 19.575 11.34 19.845 ;
     RECT  0.54 20.115 11.34 20.385 ;
     RECT  0.54 20.655 11.34 20.925 ;
     RECT  0.54 21.195 11.34 21.465 ;
     RECT  0.54 21.735 11.34 22.005 ;
     RECT  0.54 22.275 11.34 22.545 ;
     RECT  0.54 22.815 11.34 23.085 ;
     RECT  0.54 23.355 11.34 23.625 ;
     RECT  0.54 23.895 11.34 24.165 ;
     RECT  0.54 24.435 11.34 24.705 ;
     RECT  0.54 24.975 11.34 25.245 ;
     RECT  0.54 25.515 11.34 25.785 ;
     RECT  0.54 26.055 11.34 26.325 ;
     RECT  0.54 26.595 11.34 26.865 ;
     RECT  0.54 27.135 11.34 27.405 ;
    LAYER M1 ;
     RECT  0.54 0.531 11.34 27.549 ;
    LAYER M2 ;
     RECT  0.211 0.612 0.247 20.34 ;
     RECT  0.211 21.132 0.247 26.118 ;
     RECT  0.247 0.612 0.54 26.118 ;
     RECT  0.54 0.531 11.34 27.549 ;
    LAYER M3 ;
     RECT  0.795 0.523 0.885 0.571 ;
     RECT  10.836 0.379 10.854 0.571 ;
     RECT  0.216 0.571 0.885 0.715 ;
     RECT  1.656 0.379 1.674 0.715 ;
     RECT  9.684 0.751 9.702 0.763 ;
     RECT  6.195 0.523 6.285 0.793 ;
     RECT  7.128 0.751 7.146 0.793 ;
     RECT  8.028 0.841 8.046 0.913 ;
     RECT  4.896 0.715 4.914 0.949 ;
     RECT  9.648 0.763 9.702 0.955 ;
     RECT  10.836 0.571 10.89 0.955 ;
     RECT  3.06 0.751 3.078 0.985 ;
     RECT  4.716 0.949 4.914 0.985 ;
     RECT  8.028 0.913 8.37 0.985 ;
     RECT  2.988 0.985 3.078 1.021 ;
     RECT  4.5 0.985 4.914 1.021 ;
     RECT  7.956 0.985 8.37 1.021 ;
     RECT  9.648 0.955 10.89 1.049 ;
     RECT  2.448 1.021 3.078 1.099 ;
     RECT  4.428 1.021 4.914 1.139 ;
     RECT  9.684 1.049 10.89 1.181 ;
     RECT  6.195 0.793 7.146 1.255 ;
     RECT  2.448 1.099 3.51 1.381 ;
     RECT  5.652 1.255 7.146 1.381 ;
     RECT  2.448 1.381 4.374 1.409 ;
     RECT  5.22 1.381 7.146 1.453 ;
     RECT  7.956 1.021 8.514 1.453 ;
     RECT  5.22 1.453 8.514 1.517 ;
     RECT  0.216 0.715 1.674 1.525 ;
     RECT  5.652 1.517 8.514 1.525 ;
     RECT  2.772 1.409 4.374 1.553 ;
     RECT  5.652 1.525 8.73 1.565 ;
     RECT  3.096 1.553 4.374 1.589 ;
     RECT  6.048 1.565 8.73 1.589 ;
     RECT  9.936 1.181 10.89 1.589 ;
     RECT  10.44 1.589 10.89 1.651 ;
     RECT  3.42 1.589 4.374 1.679 ;
     RECT  7.236 1.589 8.73 1.679 ;
     RECT  10.44 1.651 10.998 1.687 ;
     RECT  0.216 1.525 1.89 1.715 ;
     RECT  7.236 1.679 8.586 1.715 ;
     RECT  6.048 1.589 6.477 1.751 ;
     RECT  10.44 1.687 11.214 1.757 ;
     RECT  3.888 1.679 4.374 1.949 ;
     RECT  7.236 1.715 8.046 1.949 ;
     RECT  7.236 1.949 7.902 2.285 ;
     RECT  6.195 1.751 6.477 2.371 ;
     RECT  2.268 2.371 2.286 2.489 ;
     RECT  10.584 1.757 11.214 2.525 ;
     RECT  8.82 2.491 8.838 2.531 ;
     RECT  3.888 1.949 3.906 2.605 ;
     RECT  3.492 2.605 3.906 2.633 ;
     RECT  10.584 2.525 10.926 2.717 ;
     RECT  7.668 2.285 7.902 2.731 ;
     RECT  10.584 2.717 10.854 2.731 ;
     RECT  3.492 2.633 3.51 2.767 ;
     RECT  3.456 2.767 3.51 2.795 ;
     RECT  7.668 2.731 8.01 2.831 ;
     RECT  7.668 2.831 7.83 3.029 ;
     RECT  9.468 3.001 9.486 3.101 ;
     RECT  3.456 2.795 3.474 3.109 ;
     RECT  2.808 3.109 3.474 3.149 ;
     RECT  2.844 3.149 3.474 3.209 ;
     RECT  5.292 3.181 5.31 3.271 ;
     RECT  6.195 2.371 6.93 3.271 ;
     RECT  2.844 3.209 3.294 3.335 ;
     RECT  5.292 3.271 6.93 3.335 ;
     RECT  5.544 3.335 6.93 3.371 ;
     RECT  5.544 3.371 6.477 3.407 ;
     RECT  10.26 2.731 10.854 3.485 ;
     RECT  1.944 2.911 1.962 3.569 ;
     RECT  9.684 3.811 9.702 3.869 ;
     RECT  2.844 3.335 2.97 3.911 ;
     RECT  5.688 3.407 6.477 4.109 ;
     RECT  9.648 4.027 9.666 4.109 ;
     RECT  8.064 4.081 8.082 4.181 ;
     RECT  6.048 4.109 6.477 4.217 ;
     RECT  10.836 3.485 10.854 4.351 ;
     RECT  7.668 4.315 7.686 4.379 ;
     RECT  0.216 1.715 1.077 4.387 ;
     RECT  2.952 3.911 2.97 4.507 ;
     RECT  0.216 4.387 1.422 4.559 ;
     RECT  10.692 4.351 10.854 4.603 ;
     RECT  6.195 4.217 6.477 4.621 ;
     RECT  9.684 4.603 10.854 4.649 ;
     RECT  8.82 4.621 8.838 4.721 ;
     RECT  2.952 4.507 3.654 4.765 ;
     RECT  6.195 4.621 6.534 4.801 ;
     RECT  9.684 4.649 9.702 4.829 ;
     RECT  4.716 4.891 4.734 4.991 ;
     RECT  2.556 4.765 3.654 4.999 ;
     RECT  2.556 4.999 3.978 5.131 ;
     RECT  2.052 5.131 4.122 5.165 ;
     RECT  2.052 5.165 2.07 5.189 ;
     RECT  6.195 4.801 6.93 5.419 ;
     RECT  0.216 4.559 1.077 5.431 ;
     RECT  5.76 5.419 6.93 5.495 ;
     RECT  0.216 5.431 1.638 5.531 ;
     RECT  10.836 4.649 10.854 5.611 ;
     RECT  8.568 5.611 8.586 5.701 ;
     RECT  5.976 5.495 6.93 5.707 ;
     RECT  7.992 5.701 8.586 5.707 ;
     RECT  0.216 5.531 1.386 5.765 ;
     RECT  10.836 5.611 11.214 5.789 ;
     RECT  5.976 5.707 8.586 5.801 ;
     RECT  9.612 5.371 9.63 5.809 ;
     RECT  2.916 5.165 4.122 5.845 ;
     RECT  7.38 5.801 8.586 5.845 ;
     RECT  9.612 5.809 9.738 5.845 ;
     RECT  10.836 5.789 10.998 5.947 ;
     RECT  7.38 5.845 9.738 5.999 ;
     RECT  2.916 5.845 4.23 6.035 ;
     RECT  7.38 5.999 8.586 6.035 ;
     RECT  3.924 6.035 4.23 6.269 ;
     RECT  5.04 6.151 5.058 6.269 ;
     RECT  7.452 6.035 8.586 6.269 ;
     RECT  10.584 5.947 10.998 6.269 ;
     RECT  5.976 5.801 6.477 6.283 ;
     RECT  5.292 6.283 6.477 6.317 ;
     RECT  7.848 6.269 8.586 6.341 ;
     RECT  2.844 6.277 2.862 6.376 ;
     RECT  8.244 6.341 8.586 6.413 ;
     RECT  9.684 5.999 9.738 6.413 ;
     RECT  2.34 6.376 2.862 6.449 ;
     RECT  9.72 6.413 9.738 6.557 ;
     RECT  2.268 6.547 2.286 6.719 ;
     RECT  10.8 6.269 10.998 6.749 ;
     RECT  10.836 6.749 10.998 6.781 ;
     RECT  4.32 6.421 4.338 6.809 ;
     RECT  8.424 6.413 8.586 6.809 ;
     RECT  10.836 6.781 11.142 6.941 ;
     RECT  10.836 6.941 10.962 6.953 ;
     RECT  0.216 5.765 1.077 6.961 ;
     RECT  3.312 6.859 3.33 7.051 ;
     RECT  2.088 7.051 2.106 7.115 ;
     RECT  3.312 7.051 3.582 7.151 ;
     RECT  5.292 6.317 5.382 7.231 ;
     RECT  9.684 7.231 9.702 7.321 ;
     RECT  9.144 7.321 9.702 7.325 ;
     RECT  0.216 6.961 1.278 7.349 ;
     RECT  5.076 7.231 5.382 7.349 ;
     RECT  3.312 7.151 3.33 7.385 ;
     RECT  7.92 7.231 7.938 7.385 ;
     RECT  9.144 7.325 9.162 7.421 ;
     RECT  6.195 6.317 6.477 7.465 ;
     RECT  5.292 7.349 5.382 7.493 ;
     RECT  6.195 7.465 6.678 7.699 ;
     RECT  5.652 7.699 6.678 7.771 ;
     RECT  10.836 6.953 10.926 7.771 ;
     RECT  2.844 7.591 2.862 7.799 ;
     RECT  1.944 7.699 1.962 7.889 ;
     RECT  5.652 7.771 7.578 7.889 ;
     RECT  5.652 7.889 7.038 7.961 ;
     RECT  5.652 7.961 6.966 7.997 ;
     RECT  10.224 7.771 10.926 8.131 ;
     RECT  10.152 8.131 10.926 8.231 ;
     RECT  0.216 7.349 1.077 8.311 ;
     RECT  0.216 8.311 1.602 8.429 ;
     RECT  8.64 8.311 8.658 8.429 ;
     RECT  8.784 8.437 8.802 8.477 ;
     RECT  4.356 8.005 4.374 8.539 ;
     RECT  4.356 8.539 4.95 8.573 ;
     RECT  7.812 8.275 7.83 8.815 ;
     RECT  10.26 8.231 10.926 8.827 ;
     RECT  3.06 8.683 3.078 8.851 ;
     RECT  6.195 7.997 6.966 8.851 ;
     RECT  5.904 8.851 6.966 8.969 ;
     RECT  7.812 8.815 7.866 8.969 ;
     RECT  10.26 8.827 11.214 8.969 ;
     RECT  4.932 8.573 4.95 9.005 ;
     RECT  2.268 8.815 2.286 9.013 ;
     RECT  3.06 8.851 3.366 9.013 ;
     RECT  6.195 8.969 6.966 9.085 ;
     RECT  7.812 8.969 7.83 9.085 ;
     RECT  6.195 9.085 7.83 9.113 ;
     RECT  2.268 9.013 3.366 9.163 ;
     RECT  1.944 9.163 3.366 9.211 ;
     RECT  1.944 9.211 3.582 9.239 ;
     RECT  10.26 8.969 10.926 9.245 ;
     RECT  2.484 9.239 3.582 9.311 ;
     RECT  2.484 9.311 3.078 9.419 ;
     RECT  10.26 9.245 10.854 9.629 ;
     RECT  6.195 9.113 7.614 9.691 ;
     RECT  10.26 9.629 10.602 9.751 ;
     RECT  9.684 9.751 10.602 9.821 ;
     RECT  5.148 9.883 5.166 9.923 ;
     RECT  2.844 9.419 3.078 9.959 ;
     RECT  3.06 9.959 3.078 9.965 ;
     RECT  3.816 9.895 3.834 9.979 ;
     RECT  6.084 9.691 7.614 10.021 ;
     RECT  8.46 9.895 8.478 10.021 ;
     RECT  3.816 9.979 4.518 10.049 ;
     RECT  6.084 10.021 8.478 10.049 ;
     RECT  9.684 9.821 10.062 10.171 ;
     RECT  3.816 10.049 4.194 10.193 ;
     RECT  6.195 10.049 8.478 10.219 ;
     RECT  6.195 10.219 8.622 10.319 ;
     RECT  10.8 10.363 10.818 10.4 ;
     RECT  0.216 8.429 1.077 10.471 ;
     RECT  9.648 10.171 10.062 10.555 ;
     RECT  9.54 10.555 10.062 10.561 ;
     RECT  8.064 10.319 8.622 10.589 ;
     RECT  0.216 10.471 1.602 10.651 ;
     RECT  8.064 10.589 8.478 10.661 ;
     RECT  9.54 10.561 10.674 10.733 ;
     RECT  0.216 10.651 2.322 10.843 ;
     RECT  6.195 10.319 7.038 10.859 ;
     RECT  8.46 10.661 8.478 10.859 ;
     RECT  4.032 10.193 4.194 10.975 ;
     RECT  3.924 10.975 4.194 11.003 ;
     RECT  0.216 10.843 2.862 11.101 ;
     RECT  3.924 11.003 3.942 11.101 ;
     RECT  10.26 10.733 10.674 11.137 ;
     RECT  10.26 11.137 10.854 11.237 ;
     RECT  0.216 11.101 3.942 11.273 ;
     RECT  9.468 11.371 9.486 11.515 ;
     RECT  9.468 11.515 9.702 11.552 ;
     RECT  1.836 11.273 3.942 11.669 ;
     RECT  6.195 10.859 7.002 11.821 ;
     RECT  10.836 11.237 10.854 11.821 ;
     RECT  6.195 11.821 7.794 12.011 ;
     RECT  7.74 12.011 7.794 12.055 ;
     RECT  2.268 11.669 3.942 12.091 ;
     RECT  2.268 12.091 4.446 12.209 ;
     RECT  7.74 12.055 7.974 12.209 ;
     RECT  9.144 12.187 9.162 12.245 ;
     RECT  2.376 12.209 3.942 12.353 ;
     RECT  10.836 11.821 10.89 12.361 ;
     RECT  5.22 11.983 5.238 12.365 ;
     RECT  10.764 12.361 10.89 12.451 ;
     RECT  10.764 12.451 10.998 12.475 ;
     RECT  2.376 12.353 3.726 12.479 ;
     RECT  9.324 12.361 9.342 12.479 ;
     RECT  10.764 12.475 11.214 12.515 ;
     RECT  2.376 12.479 2.394 12.551 ;
     RECT  10.764 12.515 10.998 12.721 ;
     RECT  3.6 12.479 3.726 12.749 ;
     RECT  6.195 12.011 6.966 12.749 ;
     RECT  7.74 12.209 7.758 12.991 ;
     RECT  7.704 12.991 7.794 13.091 ;
     RECT  10.044 12.721 10.998 13.289 ;
     RECT  3.708 12.749 3.726 13.325 ;
     RECT  9 13.291 9.018 13.331 ;
     RECT  0.216 11.273 1.077 13.339 ;
     RECT  5.004 13.099 5.022 13.369 ;
     RECT  10.044 13.289 10.854 13.435 ;
     RECT  0.216 13.339 1.602 13.441 ;
     RECT  4.932 13.369 5.022 13.441 ;
     RECT  6.195 12.749 6.858 13.441 ;
     RECT  5.976 13.441 6.858 13.469 ;
     RECT  4.932 13.441 5.13 13.531 ;
     RECT  5.976 13.469 6.642 13.531 ;
     RECT  4.932 13.531 6.642 13.559 ;
     RECT  5.112 13.559 6.642 13.667 ;
     RECT  0.216 13.441 2.286 13.801 ;
     RECT  4.32 13.711 4.338 13.829 ;
     RECT  9.684 13.435 10.854 13.853 ;
     RECT  8.064 13.711 8.082 13.945 ;
     RECT  5.112 13.667 6.498 14.009 ;
     RECT  9.684 13.853 10.566 14.045 ;
     RECT  0.216 13.801 2.394 14.203 ;
     RECT  3.24 13.711 3.258 14.203 ;
     RECT  0.216 14.203 3.258 14.237 ;
     RECT  0.216 14.237 2.826 14.369 ;
     RECT  3.708 14.251 3.762 14.369 ;
     RECT  0.216 14.369 2.034 14.405 ;
     RECT  7.488 13.945 8.082 14.441 ;
     RECT  9.684 14.045 10.242 14.485 ;
     RECT  9.648 14.485 10.242 14.549 ;
     RECT  9.648 14.549 9.702 14.621 ;
     RECT  5.616 14.009 6.498 14.647 ;
     RECT  3.708 14.369 3.726 14.675 ;
     RECT  9.684 14.621 9.702 14.813 ;
     RECT  10.656 14.881 10.674 14.971 ;
     RECT  4.536 14.485 4.554 14.989 ;
     RECT  5.616 14.647 6.606 15.061 ;
     RECT  7.488 14.441 7.506 15.061 ;
     RECT  10.656 14.971 10.89 15.197 ;
     RECT  2.016 14.405 2.034 15.215 ;
     RECT  4.536 14.989 4.626 15.259 ;
     RECT  5.616 15.061 7.506 15.259 ;
     RECT  4.536 15.259 7.506 15.359 ;
     RECT  10.836 15.197 10.89 15.389 ;
     RECT  8.892 15.451 8.91 15.491 ;
     RECT  10.908 15.547 10.926 15.629 ;
     RECT  9.648 15.601 9.666 15.727 ;
     RECT  9.648 15.727 9.702 15.773 ;
     RECT  9.684 15.773 9.702 15.965 ;
     RECT  7.488 15.359 7.506 16.069 ;
     RECT  0.216 14.405 1.077 16.141 ;
     RECT  2.232 16.069 2.25 16.141 ;
     RECT  0.216 16.141 2.25 16.219 ;
     RECT  4.536 15.359 6.714 16.231 ;
     RECT  7.488 16.069 7.722 16.231 ;
     RECT  0.216 16.219 3.222 16.259 ;
     RECT  4.536 16.231 7.722 16.259 ;
     RECT  2.232 16.259 3.222 16.295 ;
     RECT  10.836 16.123 10.854 16.315 ;
     RECT  4.536 16.259 4.554 16.501 ;
     RECT  10.224 16.315 10.854 16.501 ;
     RECT  10.224 16.501 11.214 16.733 ;
     RECT  4.284 16.501 4.554 16.879 ;
     RECT  10.224 16.733 10.854 16.925 ;
     RECT  4.14 16.879 4.554 16.951 ;
     RECT  5.616 16.259 7.722 16.951 ;
     RECT  0.216 16.259 1.422 17.041 ;
     RECT  2.232 16.295 3.15 17.041 ;
     RECT  10.224 16.925 10.818 17.041 ;
     RECT  4.068 16.951 4.554 17.069 ;
     RECT  5.616 16.951 8.046 17.069 ;
     RECT  0.216 17.041 3.15 17.105 ;
     RECT  4.104 17.069 4.554 17.149 ;
     RECT  5.616 17.069 6.477 17.149 ;
     RECT  7.38 17.069 8.046 17.213 ;
     RECT  9.828 17.041 10.818 17.221 ;
     RECT  2.7 17.105 3.15 17.339 ;
     RECT  2.7 17.339 2.97 17.609 ;
     RECT  0.216 17.105 1.782 17.645 ;
     RECT  4.104 17.149 6.477 17.681 ;
     RECT  5.184 17.681 6.477 17.851 ;
     RECT  7.38 17.213 7.398 17.851 ;
     RECT  9.576 17.221 10.818 17.851 ;
     RECT  8.46 17.491 8.478 17.879 ;
     RECT  4.104 17.681 4.446 17.923 ;
     RECT  9.576 17.851 11.214 18.031 ;
     RECT  2.736 17.609 2.97 18.149 ;
     RECT  9.36 18.031 11.214 18.149 ;
     RECT  9.468 18.149 11.214 18.419 ;
     RECT  3.744 17.923 4.446 18.455 ;
     RECT  9.468 18.419 10.926 18.464 ;
     RECT  8.172 18.391 8.19 18.491 ;
     RECT  9.72 18.464 10.926 18.491 ;
     RECT  0.216 17.645 1.71 18.523 ;
     RECT  5.184 17.851 7.398 18.661 ;
     RECT  5.148 18.661 8.01 18.761 ;
     RECT  5.148 18.761 7.29 18.797 ;
     RECT  3.744 18.455 4.014 18.805 ;
     RECT  3.564 18.805 4.014 18.833 ;
     RECT  0.216 18.523 2.322 18.959 ;
     RECT  3.564 18.833 3.582 18.959 ;
     RECT  5.868 18.797 7.29 18.959 ;
     RECT  2.304 18.959 2.322 19.04 ;
     RECT  10.188 18.491 10.926 19.103 ;
     RECT  5.868 18.959 6.477 19.229 ;
     RECT  10.332 19.103 10.926 19.229 ;
     RECT  4.5 19.345 4.518 19.565 ;
     RECT  5.112 19.651 5.13 19.769 ;
     RECT  7.704 19.651 7.722 19.769 ;
     RECT  3.456 19.651 3.474 19.921 ;
     RECT  3.456 19.921 4.014 19.949 ;
     RECT  2.268 20.011 2.286 20.155 ;
     RECT  6.195 19.229 6.477 20.155 ;
     RECT  10.332 19.229 10.674 20.155 ;
     RECT  7.848 19.921 7.866 20.189 ;
     RECT  2.232 20.155 2.286 20.191 ;
     RECT  1.944 20.191 2.286 20.309 ;
     RECT  7.956 20.191 8.262 20.309 ;
     RECT  10.332 20.155 10.926 20.309 ;
     RECT  10.332 20.309 10.854 20.344 ;
     RECT  0.216 18.959 1.077 20.347 ;
     RECT  7.956 20.309 7.974 20.381 ;
     RECT  9.648 20.344 10.854 20.381 ;
     RECT  5.688 20.155 6.477 20.581 ;
     RECT  5.688 20.581 6.642 20.621 ;
     RECT  0.216 20.347 1.098 20.731 ;
     RECT  2.088 20.309 2.286 20.731 ;
     RECT  9.648 20.381 9.918 20.765 ;
     RECT  8.856 20.623 8.874 20.821 ;
     RECT  0.216 20.731 1.314 20.849 ;
     RECT  8.856 20.821 9.126 20.849 ;
     RECT  8.928 20.849 9.126 21.029 ;
     RECT  3.744 19.949 4.014 21.091 ;
     RECT  5.688 20.621 6.477 21.091 ;
     RECT  2.088 20.731 2.43 21.115 ;
     RECT  10.836 20.381 10.854 21.115 ;
     RECT  2.088 21.115 2.682 21.119 ;
     RECT  3.744 21.091 6.477 21.155 ;
     RECT  9.9 20.765 9.918 21.191 ;
     RECT  2.34 21.119 2.682 21.271 ;
     RECT  5.868 21.155 6.477 21.361 ;
     RECT  5.868 21.361 6.714 21.497 ;
     RECT  10.8 21.115 10.854 21.631 ;
     RECT  7.992 21.091 8.01 21.643 ;
     RECT  3.744 21.155 5.13 21.659 ;
     RECT  8.928 21.029 8.946 21.659 ;
     RECT  3.744 21.659 4.554 21.811 ;
     RECT  3.6 21.811 4.554 21.839 ;
     RECT  4.536 21.839 4.554 21.929 ;
     RECT  7.92 21.643 8.01 21.929 ;
     RECT  2.34 21.271 2.79 21.937 ;
     RECT  2.304 21.937 2.79 22.081 ;
     RECT  2.088 22.081 2.79 22.235 ;
     RECT  2.268 22.235 2.79 22.279 ;
     RECT  3.6 21.839 3.618 22.279 ;
     RECT  2.268 22.279 3.618 22.307 ;
     RECT  5.868 21.497 6.477 22.315 ;
     RECT  10.224 21.631 10.854 22.379 ;
     RECT  5.868 22.315 6.858 22.441 ;
     RECT  10.836 22.379 10.854 22.441 ;
     RECT  10.836 22.441 10.998 22.493 ;
     RECT  5.4 22.441 6.858 22.541 ;
     RECT  0.216 20.849 1.077 22.621 ;
     RECT  2.304 22.307 3.618 22.621 ;
     RECT  10.98 22.493 10.998 22.621 ;
     RECT  7.92 21.929 7.938 22.637 ;
     RECT  2.304 22.621 3.906 22.649 ;
     RECT  2.772 22.649 3.906 22.685 ;
     RECT  6.084 22.541 6.858 22.739 ;
     RECT  6.156 22.739 6.858 22.747 ;
     RECT  6.156 22.747 6.93 22.811 ;
     RECT  0.216 22.621 1.206 23.125 ;
     RECT  0.216 23.125 1.278 23.161 ;
     RECT  2.016 23.089 2.034 23.161 ;
     RECT  8.676 23.125 8.694 23.161 ;
     RECT  10.98 22.621 11.214 23.251 ;
     RECT  2.772 22.685 2.97 23.279 ;
     RECT  3.744 22.685 3.762 23.279 ;
     RECT  8.676 23.161 9.234 23.279 ;
     RECT  10.728 23.251 11.214 23.279 ;
     RECT  6.195 22.811 6.93 23.287 ;
     RECT  0.216 23.161 2.034 23.315 ;
     RECT  5.112 23.089 5.13 23.351 ;
     RECT  8.676 23.279 8.874 23.351 ;
     RECT  2.772 23.279 2.79 23.357 ;
     RECT  8.676 23.351 8.694 23.357 ;
     RECT  10.728 23.279 10.926 23.453 ;
     RECT  6.195 23.287 6.966 23.701 ;
     RECT  7.812 23.323 7.83 23.701 ;
     RECT  6.195 23.701 7.83 23.729 ;
     RECT  10.728 23.453 10.854 23.791 ;
     RECT  6.195 23.729 7.542 23.803 ;
     RECT  6.084 23.803 7.542 23.855 ;
     RECT  10.548 23.791 10.854 23.995 ;
     RECT  0.216 23.315 1.17 24.061 ;
     RECT  10.332 23.995 10.854 24.061 ;
     RECT  2.232 23.971 2.25 24.089 ;
     RECT  0.216 24.061 1.314 24.091 ;
     RECT  6.195 23.855 7.542 24.161 ;
     RECT  10.116 24.061 10.854 24.161 ;
     RECT  6.195 24.161 6.93 24.269 ;
     RECT  4.608 24.205 4.626 24.359 ;
     RECT  6.195 24.269 6.858 24.359 ;
     RECT  2.484 24.091 2.97 24.395 ;
     RECT  2.484 24.395 2.718 24.629 ;
     RECT  3.636 24.511 3.654 24.629 ;
     RECT  10.152 24.161 10.854 24.629 ;
     RECT  2.484 24.629 2.502 24.773 ;
     RECT  5.112 24.745 5.13 24.871 ;
     RECT  6.195 24.359 6.477 24.871 ;
     RECT  10.188 24.629 10.854 24.871 ;
     RECT  10.188 24.871 10.998 24.943 ;
     RECT  5.112 24.871 6.477 24.971 ;
     RECT  4.14 24.907 4.158 24.989 ;
     RECT  10.188 24.943 11.214 24.989 ;
     RECT  5.508 24.971 6.477 25.079 ;
     RECT  7.848 24.511 7.866 25.147 ;
     RECT  6.192 25.079 6.477 25.169 ;
     RECT  7.344 25.147 8.046 25.205 ;
     RECT  2.844 25.447 2.862 25.681 ;
     RECT  10.188 24.989 10.854 25.681 ;
     RECT  10.116 25.681 10.854 25.781 ;
     RECT  2.844 25.681 2.97 25.853 ;
     RECT  9.36 25.861 9.378 25.951 ;
     RECT  0.216 24.091 1.746 25.979 ;
     RECT  2.916 25.853 2.97 25.979 ;
     RECT  4.068 25.675 4.086 26.015 ;
     RECT  8.64 25.951 9.378 26.015 ;
     RECT  5.292 25.951 5.31 26.051 ;
     RECT  7.344 25.205 7.614 26.051 ;
     RECT  8.64 26.015 8.658 26.051 ;
     RECT  0.216 25.979 1.077 26.141 ;
     RECT  7.596 26.051 7.614 26.159 ;
     RECT  10.26 25.781 10.854 26.159 ;
     RECT  3.6 26.095 3.618 26.333 ;
     RECT  10.836 26.159 10.854 26.333 ;
     RECT  0.795 26.141 1.077 27.287 ;
     RECT  6.195 25.169 6.477 27.287 ;
     RECT  0.795 27.287 0.885 27.557 ;
     RECT  6.195 27.287 6.285 27.557 ;
    LAYER M4 ;
     RECT  0.156 0.384 0.788 26.328 ;
     RECT  0.788 0.384 0.892 27.552 ;
     RECT  0.892 0.384 1.084 27.282 ;
     RECT  1.084 18.528 1.109 22.008 ;
     RECT  1.084 5.04 1.397 6.408 ;
     RECT  1.084 13.344 1.613 14.952 ;
     RECT  1.084 0.384 1.685 0.408 ;
     RECT  1.613 13.824 1.757 14.952 ;
     RECT  1.084 1.68 2.003 1.704 ;
     RECT  1.084 3.12 2.003 3.528 ;
     RECT  1.397 6.384 2.077 6.408 ;
     RECT  1.084 9.024 2.293 10.68 ;
     RECT  1.109 18.528 2.333 19.56 ;
     RECT  1.109 21.216 2.333 22.008 ;
     RECT  1.757 14.208 2.339 14.952 ;
     RECT  2.077 6.384 2.369 7.08 ;
     RECT  2.333 21.216 2.405 21.96 ;
     RECT  2.405 21.216 2.653 21.528 ;
     RECT  1.084 23.808 2.761 24.984 ;
     RECT  2.003 3.12 2.837 3.144 ;
     RECT  2.761 23.328 2.867 24.984 ;
     RECT  2.293 9.024 2.937 10.872 ;
     RECT  1.397 5.04 2.941 5.16 ;
     RECT  2.867 23.808 2.981 24.984 ;
     RECT  2.937 9.024 3.049 9.96 ;
     RECT  3.049 8.688 3.089 9.96 ;
     RECT  2.293 16.224 3.233 16.248 ;
     RECT  2.339 14.208 3.269 14.232 ;
     RECT  2.369 6.864 3.341 7.08 ;
     RECT  2.941 4.512 3.349 5.16 ;
     RECT  3.089 8.688 3.377 9.912 ;
     RECT  3.341 6.864 3.395 6.888 ;
     RECT  1.084 26.304 3.629 26.328 ;
     RECT  3.349 4.512 3.665 5.736 ;
     RECT  2.653 21.12 3.733 21.528 ;
     RECT  3.589 22.656 3.733 22.68 ;
     RECT  2.981 24.96 3.877 24.984 ;
     RECT  3.733 21.12 3.881 22.68 ;
     RECT  3.881 21.696 3.923 22.68 ;
     RECT  3.665 5.136 4.025 5.736 ;
     RECT  3.877 24.96 4.097 25.704 ;
     RECT  3.377 9.888 4.124 9.912 ;
     RECT  4.025 5.664 4.165 5.736 ;
     RECT  4.097 24.96 4.169 24.984 ;
     RECT  4.165 5.664 4.211 5.784 ;
     RECT  3.377 8.688 4.211 8.712 ;
     RECT  2.833 17.616 4.417 17.64 ;
     RECT  4.417 17.52 4.501 17.64 ;
     RECT  2.333 19.536 4.529 19.56 ;
     RECT  4.501 17.088 4.588 17.64 ;
     RECT  3.481 1.104 4.745 1.128 ;
     RECT  3.923 21.696 4.957 21.72 ;
     RECT  4.345 8.544 4.961 8.568 ;
     RECT  4.993 13.104 5.209 13.128 ;
     RECT  4.211 5.76 5.281 5.784 ;
     RECT  5.209 12.336 5.544 13.128 ;
     RECT  4.588 17.28 5.605 17.64 ;
     RECT  5.281 5.76 5.749 6.312 ;
     RECT  5.749 5.424 6.037 6.312 ;
     RECT  4.124 9.888 6.037 10.104 ;
     RECT  5.641 1.536 6.188 1.56 ;
     RECT  6.037 4.08 6.188 6.312 ;
     RECT  5.641 7.968 6.188 7.992 ;
     RECT  6.037 9.456 6.188 10.104 ;
     RECT  5.544 12.336 6.188 13.656 ;
     RECT  5.125 15.936 6.188 15.96 ;
     RECT  5.605 17.28 6.188 17.928 ;
     RECT  4.957 21.6 6.188 21.72 ;
     RECT  2.981 23.808 6.188 23.832 ;
     RECT  5.101 24.912 6.188 24.936 ;
     RECT  6.188 0.528 6.292 27.552 ;
     RECT  6.292 0.798 6.484 27.282 ;
     RECT  6.484 10.032 6.851 10.2 ;
     RECT  6.484 11.376 6.851 12.744 ;
     RECT  6.484 5.04 6.869 5.784 ;
     RECT  6.869 5.04 6.941 5.736 ;
     RECT  6.484 24.912 6.947 25.176 ;
     RECT  6.851 11.376 7.013 11.4 ;
     RECT  6.484 17.904 7.301 17.928 ;
     RECT  6.484 22.752 7.453 23.928 ;
     RECT  6.851 10.176 7.517 10.2 ;
     RECT  6.484 2.256 7.628 2.28 ;
     RECT  7.628 2.256 7.715 3 ;
     RECT  7.628 4.32 7.715 4.344 ;
     RECT  6.484 20.592 7.82 20.616 ;
     RECT  7.861 21.648 7.868 21.672 ;
     RECT  7.453 22.752 7.868 23.352 ;
     RECT  7.82 20.16 7.907 20.616 ;
     RECT  7.868 21.648 7.949 23.352 ;
     RECT  7.949 22.608 7.955 23.352 ;
     RECT  6.941 5.712 8.021 5.736 ;
     RECT  6.947 25.152 8.057 25.176 ;
     RECT  7.715 2.256 8.533 2.52 ;
     RECT  7.585 10.224 8.588 10.248 ;
     RECT  8.533 1.68 8.62 2.52 ;
     RECT  7.765 13.008 8.629 13.032 ;
     RECT  8.588 10.224 8.633 10.536 ;
     RECT  8.633 10.512 8.675 10.536 ;
     RECT  7.955 23.328 8.705 23.352 ;
     RECT  7.801 8.448 8.813 8.472 ;
     RECT  8.62 2.496 8.849 2.52 ;
     RECT  8.629 12.192 8.965 13.032 ;
     RECT  8.965 12.192 9.011 13.32 ;
     RECT  9.011 13.296 9.052 13.32 ;
     RECT  9.011 12.192 9.173 12.216 ;
     RECT  9.529 10.56 9.637 10.584 ;
     RECT  7.477 15.456 9.637 15.48 ;
     RECT  9.637 0.768 9.673 0.792 ;
     RECT  9.637 4.032 9.673 4.056 ;
     RECT  9.601 5.376 9.673 5.4 ;
     RECT  9.637 10.176 9.673 10.584 ;
     RECT  9.637 14.592 9.673 15.768 ;
     RECT  9.637 20.352 9.673 20.376 ;
     RECT  9.673 7.296 9.709 7.32 ;
     RECT  10.141 24.576 10.177 24.6 ;
     RECT  9.709 6.528 10.213 7.32 ;
     RECT  9.673 13.44 10.213 15.96 ;
     RECT  9.817 17.28 10.213 17.304 ;
     RECT  9.673 3.84 10.249 5.4 ;
     RECT  10.213 6.528 10.249 8.088 ;
     RECT  9.457 18.432 10.249 18.456 ;
     RECT  10.177 24.576 10.249 25.176 ;
     RECT  10.213 13.44 10.321 17.304 ;
     RECT  10.249 24.576 10.321 25.944 ;
     RECT  10.321 13.056 10.357 17.304 ;
     RECT  10.249 18.432 10.357 18.84 ;
     RECT  9.673 0.768 10.429 1.176 ;
     RECT  10.357 13.056 10.537 18.84 ;
     RECT  9.673 20.352 10.537 20.76 ;
     RECT  10.213 22.08 10.537 22.296 ;
     RECT  10.321 24 10.537 25.944 ;
     RECT  10.429 0.768 10.573 1.752 ;
     RECT  10.249 2.88 10.573 5.4 ;
     RECT  10.249 6.528 10.573 8.664 ;
     RECT  9.673 9.984 10.573 11.544 ;
     RECT  10.537 13.056 10.753 22.296 ;
     RECT  10.537 23.808 10.789 25.944 ;
     RECT  10.573 0.768 10.825 8.664 ;
     RECT  10.573 9.792 10.825 11.544 ;
     RECT  10.753 12.672 10.825 22.296 ;
     RECT  10.789 23.808 10.825 26.136 ;
     RECT  10.825 0.384 10.897 22.488 ;
     RECT  10.825 23.616 10.897 26.328 ;
     RECT  10.897 0.384 11.724 26.328 ;
    LAYER M5 ;
     RECT  5.904 0.144 5.928 0.517 ;
     RECT  0.78 0.517 0.9 0.787 ;
     RECT  5.904 0.517 6.3 0.787 ;
     RECT  0.78 0.787 1.092 1.669 ;
     RECT  8.544 1.669 8.568 2.245 ;
     RECT  7.68 2.245 8.568 2.531 ;
     RECT  0.78 1.669 1.992 5.171 ;
     RECT  3.36 5.125 3.384 5.653 ;
     RECT  7.68 2.531 7.704 5.747 ;
     RECT  3.36 5.653 4.2 6.899 ;
     RECT  4.176 6.899 4.2 8.533 ;
     RECT  4.176 8.533 4.536 10.019 ;
     RECT  5.904 0.787 6.492 10.021 ;
     RECT  5.904 10.021 6.84 10.069 ;
     RECT  4.176 10.019 4.2 10.115 ;
     RECT  2.88 9.925 2.904 10.883 ;
     RECT  8.64 10.501 8.664 12.181 ;
     RECT  8.64 12.181 9 12.227 ;
     RECT  5.616 10.069 6.84 12.755 ;
     RECT  8.976 12.227 9 13.331 ;
     RECT  5.616 12.755 6.492 13.667 ;
     RECT  2.304 14.197 2.328 16.259 ;
     RECT  5.136 15.925 5.16 17.077 ;
     RECT  4.512 17.077 5.16 17.315 ;
     RECT  4.512 17.315 4.536 17.555 ;
     RECT  3.792 17.605 3.816 21.155 ;
     RECT  7.872 20.149 7.896 21.683 ;
     RECT  6.18 13.667 6.492 23.317 ;
     RECT  7.92 22.597 7.944 23.363 ;
     RECT  6.18 23.317 6.936 23.893 ;
     RECT  2.832 23.317 2.856 24.611 ;
     RECT  6.18 23.893 7.416 25.187 ;
     RECT  3.888 22.645 3.912 25.715 ;
     RECT  0.78 5.171 1.092 27.293 ;
     RECT  6.18 25.187 6.492 27.293 ;
     RECT  0.78 27.293 0.9 27.563 ;
     RECT  6.18 27.293 6.3 27.563 ;
    LAYER M6 ;
     RECT  0.54 0.996 11.34 1.86 ;
     RECT  0.54 6.396 11.34 7.26 ;
     RECT  0.54 11.796 11.34 12.66 ;
     RECT  0.54 17.196 11.34 18.06 ;
     RECT  0.54 22.596 11.34 23.46 ;
  END
END ot_attn_bank_ew136
END LIBRARY
